VERSION 5.8 ;
BUSBITCHARS "[]" ;
DIVIDERCHAR "/" ;
UNITS
    DATABASE MICRONS 1000 ;
END UNITS

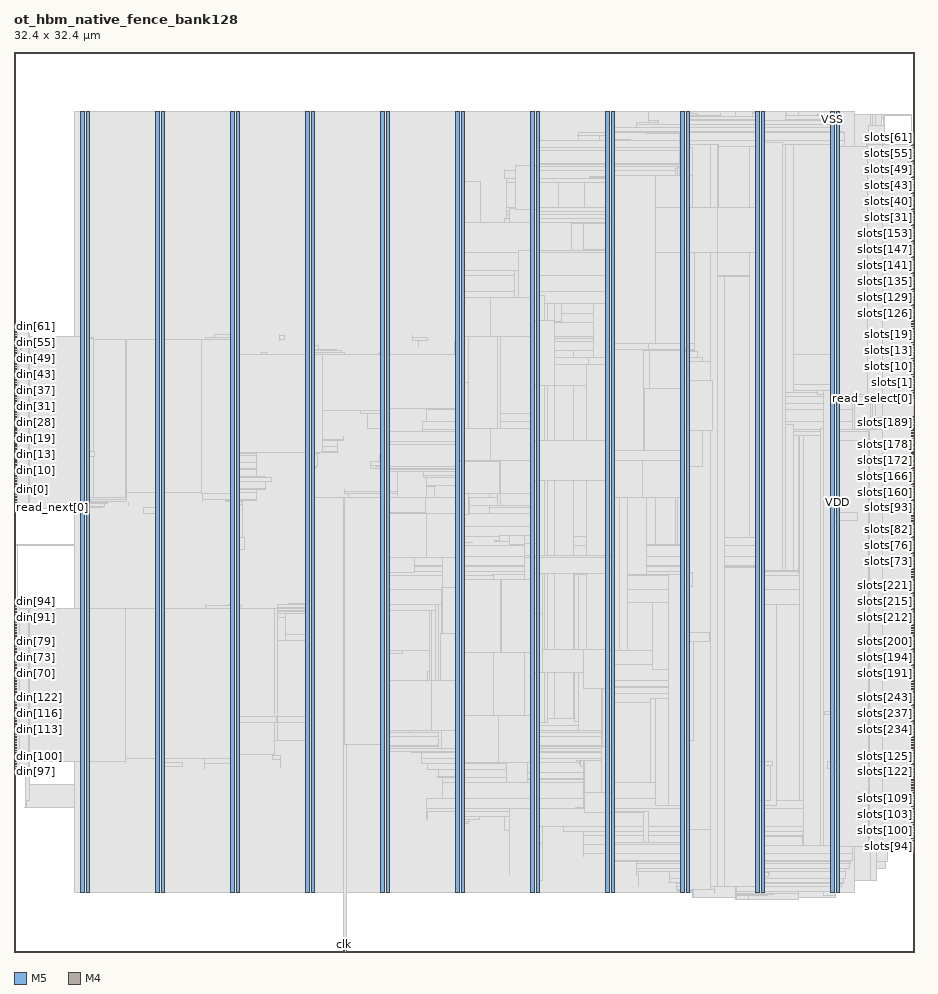
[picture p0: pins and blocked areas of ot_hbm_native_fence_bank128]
MACRO ot_hbm_native_fence_bank128
  FOREIGN ot_hbm_native_fence_bank128 0 0 ;
  CLASS BLOCK ;
  SIZE 32.4 BY 32.4 ;
  PIN clk
    DIRECTION INPUT ;
    USE SIGNAL ;
    PORT
      LAYER M5 ;
        RECT  11.856 0 11.88 0.084 ;
    END
  END clk
  PIN din[0]
    DIRECTION INPUT ;
    USE SIGNAL ;
    PORT
      LAYER M4 ;
        RECT  0 16.368 0.084 16.392 ;
    END
  END din[0]
  PIN din[100]
    DIRECTION INPUT ;
    USE SIGNAL ;
    PORT
      LAYER M4 ;
        RECT  0 6.768 0.084 6.792 ;
    END
  END din[100]
  PIN din[101]
    DIRECTION INPUT ;
    USE SIGNAL ;
    PORT
      LAYER M4 ;
        RECT  0 6.864 0.084 6.888 ;
    END
  END din[101]
  PIN din[102]
    DIRECTION INPUT ;
    USE SIGNAL ;
    PORT
      LAYER M4 ;
        RECT  0 6.96 0.084 6.984 ;
    END
  END din[102]
  PIN din[103]
    DIRECTION INPUT ;
    USE SIGNAL ;
    PORT
      LAYER M4 ;
        RECT  0 7.056 0.084 7.08 ;
    END
  END din[103]
  PIN din[104]
    DIRECTION INPUT ;
    USE SIGNAL ;
    PORT
      LAYER M4 ;
        RECT  0 7.152 0.084 7.176 ;
    END
  END din[104]
  PIN din[105]
    DIRECTION INPUT ;
    USE SIGNAL ;
    PORT
      LAYER M4 ;
        RECT  0 7.248 0.084 7.272 ;
    END
  END din[105]
  PIN din[106]
    DIRECTION INPUT ;
    USE SIGNAL ;
    PORT
      LAYER M4 ;
        RECT  0 7.344 0.084 7.368 ;
    END
  END din[106]
  PIN din[107]
    DIRECTION INPUT ;
    USE SIGNAL ;
    PORT
      LAYER M4 ;
        RECT  0 7.44 0.084 7.464 ;
    END
  END din[107]
  PIN din[108]
    DIRECTION INPUT ;
    USE SIGNAL ;
    PORT
      LAYER M4 ;
        RECT  0 7.536 0.084 7.56 ;
    END
  END din[108]
  PIN din[109]
    DIRECTION INPUT ;
    USE SIGNAL ;
    PORT
      LAYER M4 ;
        RECT  0 7.632 0.084 7.656 ;
    END
  END din[109]
  PIN din[10]
    DIRECTION INPUT ;
    USE SIGNAL ;
    PORT
      LAYER M4 ;
        RECT  0 17.328 0.084 17.352 ;
    END
  END din[10]
  PIN din[110]
    DIRECTION INPUT ;
    USE SIGNAL ;
    PORT
      LAYER M4 ;
        RECT  0 7.728 0.084 7.752 ;
    END
  END din[110]
  PIN din[111]
    DIRECTION INPUT ;
    USE SIGNAL ;
    PORT
      LAYER M4 ;
        RECT  0 7.824 0.084 7.848 ;
    END
  END din[111]
  PIN din[112]
    DIRECTION INPUT ;
    USE SIGNAL ;
    PORT
      LAYER M4 ;
        RECT  0 7.92 0.084 7.944 ;
    END
  END din[112]
  PIN din[113]
    DIRECTION INPUT ;
    USE SIGNAL ;
    PORT
      LAYER M4 ;
        RECT  0 8.016 0.084 8.04 ;
    END
  END din[113]
  PIN din[114]
    DIRECTION INPUT ;
    USE SIGNAL ;
    PORT
      LAYER M4 ;
        RECT  0 8.112 0.084 8.136 ;
    END
  END din[114]
  PIN din[115]
    DIRECTION INPUT ;
    USE SIGNAL ;
    PORT
      LAYER M4 ;
        RECT  0 8.208 0.084 8.232 ;
    END
  END din[115]
  PIN din[116]
    DIRECTION INPUT ;
    USE SIGNAL ;
    PORT
      LAYER M4 ;
        RECT  0 8.304 0.084 8.328 ;
    END
  END din[116]
  PIN din[117]
    DIRECTION INPUT ;
    USE SIGNAL ;
    PORT
      LAYER M4 ;
        RECT  0 8.4 0.084 8.424 ;
    END
  END din[117]
  PIN din[118]
    DIRECTION INPUT ;
    USE SIGNAL ;
    PORT
      LAYER M4 ;
        RECT  0 8.496 0.084 8.52 ;
    END
  END din[118]
  PIN din[119]
    DIRECTION INPUT ;
    USE SIGNAL ;
    PORT
      LAYER M4 ;
        RECT  0 8.592 0.084 8.616 ;
    END
  END din[119]
  PIN din[11]
    DIRECTION INPUT ;
    USE SIGNAL ;
    PORT
      LAYER M4 ;
        RECT  0 17.424 0.084 17.448 ;
    END
  END din[11]
  PIN din[120]
    DIRECTION INPUT ;
    USE SIGNAL ;
    PORT
      LAYER M4 ;
        RECT  0 8.688 0.084 8.712 ;
    END
  END din[120]
  PIN din[121]
    DIRECTION INPUT ;
    USE SIGNAL ;
    PORT
      LAYER M4 ;
        RECT  0 8.784 0.084 8.808 ;
    END
  END din[121]
  PIN din[122]
    DIRECTION INPUT ;
    USE SIGNAL ;
    PORT
      LAYER M4 ;
        RECT  0 8.88 0.084 8.904 ;
    END
  END din[122]
  PIN din[123]
    DIRECTION INPUT ;
    USE SIGNAL ;
    PORT
      LAYER M4 ;
        RECT  0 8.976 0.084 9 ;
    END
  END din[123]
  PIN din[124]
    DIRECTION INPUT ;
    USE SIGNAL ;
    PORT
      LAYER M4 ;
        RECT  0 9.072 0.084 9.096 ;
    END
  END din[124]
  PIN din[125]
    DIRECTION INPUT ;
    USE SIGNAL ;
    PORT
      LAYER M4 ;
        RECT  0 9.168 0.084 9.192 ;
    END
  END din[125]
  PIN din[126]
    DIRECTION INPUT ;
    USE SIGNAL ;
    PORT
      LAYER M4 ;
        RECT  0 9.264 0.084 9.288 ;
    END
  END din[126]
  PIN din[127]
    DIRECTION INPUT ;
    USE SIGNAL ;
    PORT
      LAYER M4 ;
        RECT  0 9.36 0.084 9.384 ;
    END
  END din[127]
  PIN din[12]
    DIRECTION INPUT ;
    USE SIGNAL ;
    PORT
      LAYER M4 ;
        RECT  0 17.52 0.084 17.544 ;
    END
  END din[12]
  PIN din[13]
    DIRECTION INPUT ;
    USE SIGNAL ;
    PORT
      LAYER M4 ;
        RECT  0 17.616 0.084 17.64 ;
    END
  END din[13]
  PIN din[14]
    DIRECTION INPUT ;
    USE SIGNAL ;
    PORT
      LAYER M4 ;
        RECT  0 17.712 0.084 17.736 ;
    END
  END din[14]
  PIN din[15]
    DIRECTION INPUT ;
    USE SIGNAL ;
    PORT
      LAYER M4 ;
        RECT  0 17.808 0.084 17.832 ;
    END
  END din[15]
  PIN din[16]
    DIRECTION INPUT ;
    USE SIGNAL ;
    PORT
      LAYER M4 ;
        RECT  0 17.904 0.084 17.928 ;
    END
  END din[16]
  PIN din[17]
    DIRECTION INPUT ;
    USE SIGNAL ;
    PORT
      LAYER M4 ;
        RECT  0 18 0.084 18.024 ;
    END
  END din[17]
  PIN din[18]
    DIRECTION INPUT ;
    USE SIGNAL ;
    PORT
      LAYER M4 ;
        RECT  0 18.096 0.084 18.12 ;
    END
  END din[18]
  PIN din[19]
    DIRECTION INPUT ;
    USE SIGNAL ;
    PORT
      LAYER M4 ;
        RECT  0 18.192 0.084 18.216 ;
    END
  END din[19]
  PIN din[1]
    DIRECTION INPUT ;
    USE SIGNAL ;
    PORT
      LAYER M4 ;
        RECT  0 16.464 0.084 16.488 ;
    END
  END din[1]
  PIN din[20]
    DIRECTION INPUT ;
    USE SIGNAL ;
    PORT
      LAYER M4 ;
        RECT  0 18.288 0.084 18.312 ;
    END
  END din[20]
  PIN din[21]
    DIRECTION INPUT ;
    USE SIGNAL ;
    PORT
      LAYER M4 ;
        RECT  0 18.384 0.084 18.408 ;
    END
  END din[21]
  PIN din[22]
    DIRECTION INPUT ;
    USE SIGNAL ;
    PORT
      LAYER M4 ;
        RECT  0 18.48 0.084 18.504 ;
    END
  END din[22]
  PIN din[23]
    DIRECTION INPUT ;
    USE SIGNAL ;
    PORT
      LAYER M4 ;
        RECT  0 18.576 0.084 18.6 ;
    END
  END din[23]
  PIN din[24]
    DIRECTION INPUT ;
    USE SIGNAL ;
    PORT
      LAYER M4 ;
        RECT  0 18.672 0.084 18.696 ;
    END
  END din[24]
  PIN din[25]
    DIRECTION INPUT ;
    USE SIGNAL ;
    PORT
      LAYER M4 ;
        RECT  0 18.768 0.084 18.792 ;
    END
  END din[25]
  PIN din[26]
    DIRECTION INPUT ;
    USE SIGNAL ;
    PORT
      LAYER M4 ;
        RECT  0 18.864 0.084 18.888 ;
    END
  END din[26]
  PIN din[27]
    DIRECTION INPUT ;
    USE SIGNAL ;
    PORT
      LAYER M4 ;
        RECT  0 18.96 0.084 18.984 ;
    END
  END din[27]
  PIN din[28]
    DIRECTION INPUT ;
    USE SIGNAL ;
    PORT
      LAYER M4 ;
        RECT  0 19.056 0.084 19.08 ;
    END
  END din[28]
  PIN din[29]
    DIRECTION INPUT ;
    USE SIGNAL ;
    PORT
      LAYER M4 ;
        RECT  0 19.152 0.084 19.176 ;
    END
  END din[29]
  PIN din[2]
    DIRECTION INPUT ;
    USE SIGNAL ;
    PORT
      LAYER M4 ;
        RECT  0 16.56 0.084 16.584 ;
    END
  END din[2]
  PIN din[30]
    DIRECTION INPUT ;
    USE SIGNAL ;
    PORT
      LAYER M4 ;
        RECT  0 19.248 0.084 19.272 ;
    END
  END din[30]
  PIN din[31]
    DIRECTION INPUT ;
    USE SIGNAL ;
    PORT
      LAYER M4 ;
        RECT  0 19.344 0.084 19.368 ;
    END
  END din[31]
  PIN din[32]
    DIRECTION INPUT ;
    USE SIGNAL ;
    PORT
      LAYER M4 ;
        RECT  0 19.44 0.084 19.464 ;
    END
  END din[32]
  PIN din[33]
    DIRECTION INPUT ;
    USE SIGNAL ;
    PORT
      LAYER M4 ;
        RECT  0 19.536 0.084 19.56 ;
    END
  END din[33]
  PIN din[34]
    DIRECTION INPUT ;
    USE SIGNAL ;
    PORT
      LAYER M4 ;
        RECT  0 19.632 0.084 19.656 ;
    END
  END din[34]
  PIN din[35]
    DIRECTION INPUT ;
    USE SIGNAL ;
    PORT
      LAYER M4 ;
        RECT  0 19.728 0.084 19.752 ;
    END
  END din[35]
  PIN din[36]
    DIRECTION INPUT ;
    USE SIGNAL ;
    PORT
      LAYER M4 ;
        RECT  0 19.824 0.084 19.848 ;
    END
  END din[36]
  PIN din[37]
    DIRECTION INPUT ;
    USE SIGNAL ;
    PORT
      LAYER M4 ;
        RECT  0 19.92 0.084 19.944 ;
    END
  END din[37]
  PIN din[38]
    DIRECTION INPUT ;
    USE SIGNAL ;
    PORT
      LAYER M4 ;
        RECT  0 20.016 0.084 20.04 ;
    END
  END din[38]
  PIN din[39]
    DIRECTION INPUT ;
    USE SIGNAL ;
    PORT
      LAYER M4 ;
        RECT  0 20.112 0.084 20.136 ;
    END
  END din[39]
  PIN din[3]
    DIRECTION INPUT ;
    USE SIGNAL ;
    PORT
      LAYER M4 ;
        RECT  0 16.656 0.084 16.68 ;
    END
  END din[3]
  PIN din[40]
    DIRECTION INPUT ;
    USE SIGNAL ;
    PORT
      LAYER M4 ;
        RECT  0 20.208 0.084 20.232 ;
    END
  END din[40]
  PIN din[41]
    DIRECTION INPUT ;
    USE SIGNAL ;
    PORT
      LAYER M4 ;
        RECT  0 20.304 0.084 20.328 ;
    END
  END din[41]
  PIN din[42]
    DIRECTION INPUT ;
    USE SIGNAL ;
    PORT
      LAYER M4 ;
        RECT  0 20.4 0.084 20.424 ;
    END
  END din[42]
  PIN din[43]
    DIRECTION INPUT ;
    USE SIGNAL ;
    PORT
      LAYER M4 ;
        RECT  0 20.496 0.084 20.52 ;
    END
  END din[43]
  PIN din[44]
    DIRECTION INPUT ;
    USE SIGNAL ;
    PORT
      LAYER M4 ;
        RECT  0 20.592 0.084 20.616 ;
    END
  END din[44]
  PIN din[45]
    DIRECTION INPUT ;
    USE SIGNAL ;
    PORT
      LAYER M4 ;
        RECT  0 20.688 0.084 20.712 ;
    END
  END din[45]
  PIN din[46]
    DIRECTION INPUT ;
    USE SIGNAL ;
    PORT
      LAYER M4 ;
        RECT  0 20.784 0.084 20.808 ;
    END
  END din[46]
  PIN din[47]
    DIRECTION INPUT ;
    USE SIGNAL ;
    PORT
      LAYER M4 ;
        RECT  0 20.88 0.084 20.904 ;
    END
  END din[47]
  PIN din[48]
    DIRECTION INPUT ;
    USE SIGNAL ;
    PORT
      LAYER M4 ;
        RECT  0 20.976 0.084 21 ;
    END
  END din[48]
  PIN din[49]
    DIRECTION INPUT ;
    USE SIGNAL ;
    PORT
      LAYER M4 ;
        RECT  0 21.072 0.084 21.096 ;
    END
  END din[49]
  PIN din[4]
    DIRECTION INPUT ;
    USE SIGNAL ;
    PORT
      LAYER M4 ;
        RECT  0 16.752 0.084 16.776 ;
    END
  END din[4]
  PIN din[50]
    DIRECTION INPUT ;
    USE SIGNAL ;
    PORT
      LAYER M4 ;
        RECT  0 21.168 0.084 21.192 ;
    END
  END din[50]
  PIN din[51]
    DIRECTION INPUT ;
    USE SIGNAL ;
    PORT
      LAYER M4 ;
        RECT  0 21.264 0.084 21.288 ;
    END
  END din[51]
  PIN din[52]
    DIRECTION INPUT ;
    USE SIGNAL ;
    PORT
      LAYER M4 ;
        RECT  0 21.36 0.084 21.384 ;
    END
  END din[52]
  PIN din[53]
    DIRECTION INPUT ;
    USE SIGNAL ;
    PORT
      LAYER M4 ;
        RECT  0 21.456 0.084 21.48 ;
    END
  END din[53]
  PIN din[54]
    DIRECTION INPUT ;
    USE SIGNAL ;
    PORT
      LAYER M4 ;
        RECT  0 21.552 0.084 21.576 ;
    END
  END din[54]
  PIN din[55]
    DIRECTION INPUT ;
    USE SIGNAL ;
    PORT
      LAYER M4 ;
        RECT  0 21.648 0.084 21.672 ;
    END
  END din[55]
  PIN din[56]
    DIRECTION INPUT ;
    USE SIGNAL ;
    PORT
      LAYER M4 ;
        RECT  0 21.744 0.084 21.768 ;
    END
  END din[56]
  PIN din[57]
    DIRECTION INPUT ;
    USE SIGNAL ;
    PORT
      LAYER M4 ;
        RECT  0 21.84 0.084 21.864 ;
    END
  END din[57]
  PIN din[58]
    DIRECTION INPUT ;
    USE SIGNAL ;
    PORT
      LAYER M4 ;
        RECT  0 21.936 0.084 21.96 ;
    END
  END din[58]
  PIN din[59]
    DIRECTION INPUT ;
    USE SIGNAL ;
    PORT
      LAYER M4 ;
        RECT  0 22.032 0.084 22.056 ;
    END
  END din[59]
  PIN din[5]
    DIRECTION INPUT ;
    USE SIGNAL ;
    PORT
      LAYER M4 ;
        RECT  0 16.848 0.084 16.872 ;
    END
  END din[5]
  PIN din[60]
    DIRECTION INPUT ;
    USE SIGNAL ;
    PORT
      LAYER M4 ;
        RECT  0 22.128 0.084 22.152 ;
    END
  END din[60]
  PIN din[61]
    DIRECTION INPUT ;
    USE SIGNAL ;
    PORT
      LAYER M4 ;
        RECT  0 22.224 0.084 22.248 ;
    END
  END din[61]
  PIN din[62]
    DIRECTION INPUT ;
    USE SIGNAL ;
    PORT
      LAYER M4 ;
        RECT  0 22.32 0.084 22.344 ;
    END
  END din[62]
  PIN din[63]
    DIRECTION INPUT ;
    USE SIGNAL ;
    PORT
      LAYER M4 ;
        RECT  0 22.416 0.084 22.44 ;
    END
  END din[63]
  PIN din[64]
    DIRECTION INPUT ;
    USE SIGNAL ;
    PORT
      LAYER M4 ;
        RECT  0 9.456 0.084 9.48 ;
    END
  END din[64]
  PIN din[65]
    DIRECTION INPUT ;
    USE SIGNAL ;
    PORT
      LAYER M4 ;
        RECT  0 9.552 0.084 9.576 ;
    END
  END din[65]
  PIN din[66]
    DIRECTION INPUT ;
    USE SIGNAL ;
    PORT
      LAYER M4 ;
        RECT  0 9.648 0.084 9.672 ;
    END
  END din[66]
  PIN din[67]
    DIRECTION INPUT ;
    USE SIGNAL ;
    PORT
      LAYER M4 ;
        RECT  0 9.744 0.084 9.768 ;
    END
  END din[67]
  PIN din[68]
    DIRECTION INPUT ;
    USE SIGNAL ;
    PORT
      LAYER M4 ;
        RECT  0 9.84 0.084 9.864 ;
    END
  END din[68]
  PIN din[69]
    DIRECTION INPUT ;
    USE SIGNAL ;
    PORT
      LAYER M4 ;
        RECT  0 9.936 0.084 9.96 ;
    END
  END din[69]
  PIN din[6]
    DIRECTION INPUT ;
    USE SIGNAL ;
    PORT
      LAYER M4 ;
        RECT  0 16.944 0.084 16.968 ;
    END
  END din[6]
  PIN din[70]
    DIRECTION INPUT ;
    USE SIGNAL ;
    PORT
      LAYER M4 ;
        RECT  0 10.032 0.084 10.056 ;
    END
  END din[70]
  PIN din[71]
    DIRECTION INPUT ;
    USE SIGNAL ;
    PORT
      LAYER M4 ;
        RECT  0 10.128 0.084 10.152 ;
    END
  END din[71]
  PIN din[72]
    DIRECTION INPUT ;
    USE SIGNAL ;
    PORT
      LAYER M4 ;
        RECT  0 10.224 0.084 10.248 ;
    END
  END din[72]
  PIN din[73]
    DIRECTION INPUT ;
    USE SIGNAL ;
    PORT
      LAYER M4 ;
        RECT  0 10.32 0.084 10.344 ;
    END
  END din[73]
  PIN din[74]
    DIRECTION INPUT ;
    USE SIGNAL ;
    PORT
      LAYER M4 ;
        RECT  0 10.416 0.084 10.44 ;
    END
  END din[74]
  PIN din[75]
    DIRECTION INPUT ;
    USE SIGNAL ;
    PORT
      LAYER M4 ;
        RECT  0 10.512 0.084 10.536 ;
    END
  END din[75]
  PIN din[76]
    DIRECTION INPUT ;
    USE SIGNAL ;
    PORT
      LAYER M4 ;
        RECT  0 10.608 0.084 10.632 ;
    END
  END din[76]
  PIN din[77]
    DIRECTION INPUT ;
    USE SIGNAL ;
    PORT
      LAYER M4 ;
        RECT  0 10.704 0.084 10.728 ;
    END
  END din[77]
  PIN din[78]
    DIRECTION INPUT ;
    USE SIGNAL ;
    PORT
      LAYER M4 ;
        RECT  0 10.8 0.084 10.824 ;
    END
  END din[78]
  PIN din[79]
    DIRECTION INPUT ;
    USE SIGNAL ;
    PORT
      LAYER M4 ;
        RECT  0 10.896 0.084 10.92 ;
    END
  END din[79]
  PIN din[7]
    DIRECTION INPUT ;
    USE SIGNAL ;
    PORT
      LAYER M4 ;
        RECT  0 17.04 0.084 17.064 ;
    END
  END din[7]
  PIN din[80]
    DIRECTION INPUT ;
    USE SIGNAL ;
    PORT
      LAYER M4 ;
        RECT  0 10.992 0.084 11.016 ;
    END
  END din[80]
  PIN din[81]
    DIRECTION INPUT ;
    USE SIGNAL ;
    PORT
      LAYER M4 ;
        RECT  0 11.088 0.084 11.112 ;
    END
  END din[81]
  PIN din[82]
    DIRECTION INPUT ;
    USE SIGNAL ;
    PORT
      LAYER M4 ;
        RECT  0 11.184 0.084 11.208 ;
    END
  END din[82]
  PIN din[83]
    DIRECTION INPUT ;
    USE SIGNAL ;
    PORT
      LAYER M4 ;
        RECT  0 11.28 0.084 11.304 ;
    END
  END din[83]
  PIN din[84]
    DIRECTION INPUT ;
    USE SIGNAL ;
    PORT
      LAYER M4 ;
        RECT  0 11.376 0.084 11.4 ;
    END
  END din[84]
  PIN din[85]
    DIRECTION INPUT ;
    USE SIGNAL ;
    PORT
      LAYER M4 ;
        RECT  0 11.472 0.084 11.496 ;
    END
  END din[85]
  PIN din[86]
    DIRECTION INPUT ;
    USE SIGNAL ;
    PORT
      LAYER M4 ;
        RECT  0 11.568 0.084 11.592 ;
    END
  END din[86]
  PIN din[87]
    DIRECTION INPUT ;
    USE SIGNAL ;
    PORT
      LAYER M4 ;
        RECT  0 11.664 0.084 11.688 ;
    END
  END din[87]
  PIN din[88]
    DIRECTION INPUT ;
    USE SIGNAL ;
    PORT
      LAYER M4 ;
        RECT  0 11.76 0.084 11.784 ;
    END
  END din[88]
  PIN din[89]
    DIRECTION INPUT ;
    USE SIGNAL ;
    PORT
      LAYER M4 ;
        RECT  0 11.856 0.084 11.88 ;
    END
  END din[89]
  PIN din[8]
    DIRECTION INPUT ;
    USE SIGNAL ;
    PORT
      LAYER M4 ;
        RECT  0 17.136 0.084 17.16 ;
    END
  END din[8]
  PIN din[90]
    DIRECTION INPUT ;
    USE SIGNAL ;
    PORT
      LAYER M4 ;
        RECT  0 11.952 0.084 11.976 ;
    END
  END din[90]
  PIN din[91]
    DIRECTION INPUT ;
    USE SIGNAL ;
    PORT
      LAYER M4 ;
        RECT  0 12.048 0.084 12.072 ;
    END
  END din[91]
  PIN din[92]
    DIRECTION INPUT ;
    USE SIGNAL ;
    PORT
      LAYER M4 ;
        RECT  0 12.144 0.084 12.168 ;
    END
  END din[92]
  PIN din[93]
    DIRECTION INPUT ;
    USE SIGNAL ;
    PORT
      LAYER M4 ;
        RECT  0 12.24 0.084 12.264 ;
    END
  END din[93]
  PIN din[94]
    DIRECTION INPUT ;
    USE SIGNAL ;
    PORT
      LAYER M4 ;
        RECT  0 12.336 0.084 12.36 ;
    END
  END din[94]
  PIN din[95]
    DIRECTION INPUT ;
    USE SIGNAL ;
    PORT
      LAYER M4 ;
        RECT  0 12.432 0.084 12.456 ;
    END
  END din[95]
  PIN din[96]
    DIRECTION INPUT ;
    USE SIGNAL ;
    PORT
      LAYER M4 ;
        RECT  0 6.384 0.084 6.408 ;
    END
  END din[96]
  PIN din[97]
    DIRECTION INPUT ;
    USE SIGNAL ;
    PORT
      LAYER M4 ;
        RECT  0 6.48 0.084 6.504 ;
    END
  END din[97]
  PIN din[98]
    DIRECTION INPUT ;
    USE SIGNAL ;
    PORT
      LAYER M4 ;
        RECT  0 6.576 0.084 6.6 ;
    END
  END din[98]
  PIN din[99]
    DIRECTION INPUT ;
    USE SIGNAL ;
    PORT
      LAYER M4 ;
        RECT  0 6.672 0.084 6.696 ;
    END
  END din[99]
  PIN din[9]
    DIRECTION INPUT ;
    USE SIGNAL ;
    PORT
      LAYER M4 ;
        RECT  0 17.232 0.084 17.256 ;
    END
  END din[9]
  PIN read_next[0]
    DIRECTION INPUT ;
    USE SIGNAL ;
    PORT
      LAYER M4 ;
        RECT  0 15.984 0.084 16.008 ;
    END
  END read_next[0]
  PIN read_next[1]
    DIRECTION INPUT ;
    USE SIGNAL ;
    PORT
      LAYER M4 ;
        RECT  0 16.08 0.084 16.104 ;
    END
  END read_next[1]
  PIN read_select[0]
    DIRECTION OUTPUT ;
    USE SIGNAL ;
    PORT
      LAYER M4 ;
        RECT  32.316 19.92 32.4 19.944 ;
    END
  END read_select[0]
  PIN read_select[1]
    DIRECTION OUTPUT ;
    USE SIGNAL ;
    PORT
      LAYER M4 ;
        RECT  32.316 20.016 32.4 20.04 ;
    END
  END read_select[1]
  PIN rst_n
    DIRECTION INPUT ;
    USE SIGNAL ;
    PORT
      LAYER M5 ;
        RECT  11.952 0 11.976 0.084 ;
    END
  END rst_n
  PIN slots[0]
    DIRECTION OUTPUT ;
    USE SIGNAL ;
    PORT
      LAYER M4 ;
        RECT  32.316 20.112 32.4 20.136 ;
    END
  END slots[0]
  PIN slots[100]
    DIRECTION OUTPUT ;
    USE SIGNAL ;
    PORT
      LAYER M4 ;
        RECT  32.316 4.368 32.4 4.392 ;
    END
  END slots[100]
  PIN slots[101]
    DIRECTION OUTPUT ;
    USE SIGNAL ;
    PORT
      LAYER M4 ;
        RECT  32.316 4.464 32.4 4.488 ;
    END
  END slots[101]
  PIN slots[102]
    DIRECTION OUTPUT ;
    USE SIGNAL ;
    PORT
      LAYER M4 ;
        RECT  32.316 4.56 32.4 4.584 ;
    END
  END slots[102]
  PIN slots[103]
    DIRECTION OUTPUT ;
    USE SIGNAL ;
    PORT
      LAYER M4 ;
        RECT  32.316 4.656 32.4 4.68 ;
    END
  END slots[103]
  PIN slots[104]
    DIRECTION OUTPUT ;
    USE SIGNAL ;
    PORT
      LAYER M4 ;
        RECT  32.316 4.752 32.4 4.776 ;
    END
  END slots[104]
  PIN slots[105]
    DIRECTION OUTPUT ;
    USE SIGNAL ;
    PORT
      LAYER M4 ;
        RECT  32.316 4.848 32.4 4.872 ;
    END
  END slots[105]
  PIN slots[106]
    DIRECTION OUTPUT ;
    USE SIGNAL ;
    PORT
      LAYER M4 ;
        RECT  32.316 4.944 32.4 4.968 ;
    END
  END slots[106]
  PIN slots[107]
    DIRECTION OUTPUT ;
    USE SIGNAL ;
    PORT
      LAYER M4 ;
        RECT  32.316 5.04 32.4 5.064 ;
    END
  END slots[107]
  PIN slots[108]
    DIRECTION OUTPUT ;
    USE SIGNAL ;
    PORT
      LAYER M4 ;
        RECT  32.316 5.136 32.4 5.16 ;
    END
  END slots[108]
  PIN slots[109]
    DIRECTION OUTPUT ;
    USE SIGNAL ;
    PORT
      LAYER M4 ;
        RECT  32.316 5.232 32.4 5.256 ;
    END
  END slots[109]
  PIN slots[10]
    DIRECTION OUTPUT ;
    USE SIGNAL ;
    PORT
      LAYER M4 ;
        RECT  32.316 21.072 32.4 21.096 ;
    END
  END slots[10]
  PIN slots[110]
    DIRECTION OUTPUT ;
    USE SIGNAL ;
    PORT
      LAYER M4 ;
        RECT  32.316 5.328 32.4 5.352 ;
    END
  END slots[110]
  PIN slots[111]
    DIRECTION OUTPUT ;
    USE SIGNAL ;
    PORT
      LAYER M4 ;
        RECT  32.316 5.424 32.4 5.448 ;
    END
  END slots[111]
  PIN slots[112]
    DIRECTION OUTPUT ;
    USE SIGNAL ;
    PORT
      LAYER M4 ;
        RECT  32.316 5.52 32.4 5.544 ;
    END
  END slots[112]
  PIN slots[113]
    DIRECTION OUTPUT ;
    USE SIGNAL ;
    PORT
      LAYER M4 ;
        RECT  32.316 5.616 32.4 5.64 ;
    END
  END slots[113]
  PIN slots[114]
    DIRECTION OUTPUT ;
    USE SIGNAL ;
    PORT
      LAYER M4 ;
        RECT  32.316 5.712 32.4 5.736 ;
    END
  END slots[114]
  PIN slots[115]
    DIRECTION OUTPUT ;
    USE SIGNAL ;
    PORT
      LAYER M4 ;
        RECT  32.316 5.808 32.4 5.832 ;
    END
  END slots[115]
  PIN slots[116]
    DIRECTION OUTPUT ;
    USE SIGNAL ;
    PORT
      LAYER M4 ;
        RECT  32.316 5.904 32.4 5.928 ;
    END
  END slots[116]
  PIN slots[117]
    DIRECTION OUTPUT ;
    USE SIGNAL ;
    PORT
      LAYER M4 ;
        RECT  32.316 6 32.4 6.024 ;
    END
  END slots[117]
  PIN slots[118]
    DIRECTION OUTPUT ;
    USE SIGNAL ;
    PORT
      LAYER M4 ;
        RECT  32.316 6.096 32.4 6.12 ;
    END
  END slots[118]
  PIN slots[119]
    DIRECTION OUTPUT ;
    USE SIGNAL ;
    PORT
      LAYER M4 ;
        RECT  32.316 6.192 32.4 6.216 ;
    END
  END slots[119]
  PIN slots[11]
    DIRECTION OUTPUT ;
    USE SIGNAL ;
    PORT
      LAYER M4 ;
        RECT  32.316 21.168 32.4 21.192 ;
    END
  END slots[11]
  PIN slots[120]
    DIRECTION OUTPUT ;
    USE SIGNAL ;
    PORT
      LAYER M4 ;
        RECT  32.316 6.288 32.4 6.312 ;
    END
  END slots[120]
  PIN slots[121]
    DIRECTION OUTPUT ;
    USE SIGNAL ;
    PORT
      LAYER M4 ;
        RECT  32.316 6.384 32.4 6.408 ;
    END
  END slots[121]
  PIN slots[122]
    DIRECTION OUTPUT ;
    USE SIGNAL ;
    PORT
      LAYER M4 ;
        RECT  32.316 6.48 32.4 6.504 ;
    END
  END slots[122]
  PIN slots[123]
    DIRECTION OUTPUT ;
    USE SIGNAL ;
    PORT
      LAYER M4 ;
        RECT  32.316 6.576 32.4 6.6 ;
    END
  END slots[123]
  PIN slots[124]
    DIRECTION OUTPUT ;
    USE SIGNAL ;
    PORT
      LAYER M4 ;
        RECT  32.316 6.672 32.4 6.696 ;
    END
  END slots[124]
  PIN slots[125]
    DIRECTION OUTPUT ;
    USE SIGNAL ;
    PORT
      LAYER M4 ;
        RECT  32.316 6.768 32.4 6.792 ;
    END
  END slots[125]
  PIN slots[126]
    DIRECTION OUTPUT ;
    USE SIGNAL ;
    PORT
      LAYER M4 ;
        RECT  32.316 22.992 32.4 23.016 ;
    END
  END slots[126]
  PIN slots[127]
    DIRECTION OUTPUT ;
    USE SIGNAL ;
    PORT
      LAYER M4 ;
        RECT  32.316 23.088 32.4 23.112 ;
    END
  END slots[127]
  PIN slots[128]
    DIRECTION OUTPUT ;
    USE SIGNAL ;
    PORT
      LAYER M4 ;
        RECT  32.316 23.184 32.4 23.208 ;
    END
  END slots[128]
  PIN slots[129]
    DIRECTION OUTPUT ;
    USE SIGNAL ;
    PORT
      LAYER M4 ;
        RECT  32.316 23.28 32.4 23.304 ;
    END
  END slots[129]
  PIN slots[12]
    DIRECTION OUTPUT ;
    USE SIGNAL ;
    PORT
      LAYER M4 ;
        RECT  32.316 21.264 32.4 21.288 ;
    END
  END slots[12]
  PIN slots[130]
    DIRECTION OUTPUT ;
    USE SIGNAL ;
    PORT
      LAYER M4 ;
        RECT  32.316 23.376 32.4 23.4 ;
    END
  END slots[130]
  PIN slots[131]
    DIRECTION OUTPUT ;
    USE SIGNAL ;
    PORT
      LAYER M4 ;
        RECT  32.316 23.472 32.4 23.496 ;
    END
  END slots[131]
  PIN slots[132]
    DIRECTION OUTPUT ;
    USE SIGNAL ;
    PORT
      LAYER M4 ;
        RECT  32.316 23.568 32.4 23.592 ;
    END
  END slots[132]
  PIN slots[133]
    DIRECTION OUTPUT ;
    USE SIGNAL ;
    PORT
      LAYER M4 ;
        RECT  32.316 23.664 32.4 23.688 ;
    END
  END slots[133]
  PIN slots[134]
    DIRECTION OUTPUT ;
    USE SIGNAL ;
    PORT
      LAYER M4 ;
        RECT  32.316 23.76 32.4 23.784 ;
    END
  END slots[134]
  PIN slots[135]
    DIRECTION OUTPUT ;
    USE SIGNAL ;
    PORT
      LAYER M4 ;
        RECT  32.316 23.856 32.4 23.88 ;
    END
  END slots[135]
  PIN slots[136]
    DIRECTION OUTPUT ;
    USE SIGNAL ;
    PORT
      LAYER M4 ;
        RECT  32.316 23.952 32.4 23.976 ;
    END
  END slots[136]
  PIN slots[137]
    DIRECTION OUTPUT ;
    USE SIGNAL ;
    PORT
      LAYER M4 ;
        RECT  32.316 24.048 32.4 24.072 ;
    END
  END slots[137]
  PIN slots[138]
    DIRECTION OUTPUT ;
    USE SIGNAL ;
    PORT
      LAYER M4 ;
        RECT  32.316 24.144 32.4 24.168 ;
    END
  END slots[138]
  PIN slots[139]
    DIRECTION OUTPUT ;
    USE SIGNAL ;
    PORT
      LAYER M4 ;
        RECT  32.316 24.24 32.4 24.264 ;
    END
  END slots[139]
  PIN slots[13]
    DIRECTION OUTPUT ;
    USE SIGNAL ;
    PORT
      LAYER M4 ;
        RECT  32.316 21.36 32.4 21.384 ;
    END
  END slots[13]
  PIN slots[140]
    DIRECTION OUTPUT ;
    USE SIGNAL ;
    PORT
      LAYER M4 ;
        RECT  32.316 24.336 32.4 24.36 ;
    END
  END slots[140]
  PIN slots[141]
    DIRECTION OUTPUT ;
    USE SIGNAL ;
    PORT
      LAYER M4 ;
        RECT  32.316 24.432 32.4 24.456 ;
    END
  END slots[141]
  PIN slots[142]
    DIRECTION OUTPUT ;
    USE SIGNAL ;
    PORT
      LAYER M4 ;
        RECT  32.316 24.528 32.4 24.552 ;
    END
  END slots[142]
  PIN slots[143]
    DIRECTION OUTPUT ;
    USE SIGNAL ;
    PORT
      LAYER M4 ;
        RECT  32.316 24.624 32.4 24.648 ;
    END
  END slots[143]
  PIN slots[144]
    DIRECTION OUTPUT ;
    USE SIGNAL ;
    PORT
      LAYER M4 ;
        RECT  32.316 24.72 32.4 24.744 ;
    END
  END slots[144]
  PIN slots[145]
    DIRECTION OUTPUT ;
    USE SIGNAL ;
    PORT
      LAYER M4 ;
        RECT  32.316 24.816 32.4 24.84 ;
    END
  END slots[145]
  PIN slots[146]
    DIRECTION OUTPUT ;
    USE SIGNAL ;
    PORT
      LAYER M4 ;
        RECT  32.316 24.912 32.4 24.936 ;
    END
  END slots[146]
  PIN slots[147]
    DIRECTION OUTPUT ;
    USE SIGNAL ;
    PORT
      LAYER M4 ;
        RECT  32.316 25.008 32.4 25.032 ;
    END
  END slots[147]
  PIN slots[148]
    DIRECTION OUTPUT ;
    USE SIGNAL ;
    PORT
      LAYER M4 ;
        RECT  32.316 25.104 32.4 25.128 ;
    END
  END slots[148]
  PIN slots[149]
    DIRECTION OUTPUT ;
    USE SIGNAL ;
    PORT
      LAYER M4 ;
        RECT  32.316 25.2 32.4 25.224 ;
    END
  END slots[149]
  PIN slots[14]
    DIRECTION OUTPUT ;
    USE SIGNAL ;
    PORT
      LAYER M4 ;
        RECT  32.316 21.456 32.4 21.48 ;
    END
  END slots[14]
  PIN slots[150]
    DIRECTION OUTPUT ;
    USE SIGNAL ;
    PORT
      LAYER M4 ;
        RECT  32.316 25.296 32.4 25.32 ;
    END
  END slots[150]
  PIN slots[151]
    DIRECTION OUTPUT ;
    USE SIGNAL ;
    PORT
      LAYER M4 ;
        RECT  32.316 25.392 32.4 25.416 ;
    END
  END slots[151]
  PIN slots[152]
    DIRECTION OUTPUT ;
    USE SIGNAL ;
    PORT
      LAYER M4 ;
        RECT  32.316 25.488 32.4 25.512 ;
    END
  END slots[152]
  PIN slots[153]
    DIRECTION OUTPUT ;
    USE SIGNAL ;
    PORT
      LAYER M4 ;
        RECT  32.316 25.584 32.4 25.608 ;
    END
  END slots[153]
  PIN slots[154]
    DIRECTION OUTPUT ;
    USE SIGNAL ;
    PORT
      LAYER M4 ;
        RECT  32.316 25.68 32.4 25.704 ;
    END
  END slots[154]
  PIN slots[155]
    DIRECTION OUTPUT ;
    USE SIGNAL ;
    PORT
      LAYER M4 ;
        RECT  32.316 25.776 32.4 25.8 ;
    END
  END slots[155]
  PIN slots[156]
    DIRECTION OUTPUT ;
    USE SIGNAL ;
    PORT
      LAYER M4 ;
        RECT  32.316 25.872 32.4 25.896 ;
    END
  END slots[156]
  PIN slots[157]
    DIRECTION OUTPUT ;
    USE SIGNAL ;
    PORT
      LAYER M4 ;
        RECT  32.316 25.968 32.4 25.992 ;
    END
  END slots[157]
  PIN slots[158]
    DIRECTION OUTPUT ;
    USE SIGNAL ;
    PORT
      LAYER M4 ;
        RECT  32.316 16.08 32.4 16.104 ;
    END
  END slots[158]
  PIN slots[159]
    DIRECTION OUTPUT ;
    USE SIGNAL ;
    PORT
      LAYER M4 ;
        RECT  32.316 16.176 32.4 16.2 ;
    END
  END slots[159]
  PIN slots[15]
    DIRECTION OUTPUT ;
    USE SIGNAL ;
    PORT
      LAYER M4 ;
        RECT  32.316 21.552 32.4 21.576 ;
    END
  END slots[15]
  PIN slots[160]
    DIRECTION OUTPUT ;
    USE SIGNAL ;
    PORT
      LAYER M4 ;
        RECT  32.316 16.272 32.4 16.296 ;
    END
  END slots[160]
  PIN slots[161]
    DIRECTION OUTPUT ;
    USE SIGNAL ;
    PORT
      LAYER M4 ;
        RECT  32.316 16.368 32.4 16.392 ;
    END
  END slots[161]
  PIN slots[162]
    DIRECTION OUTPUT ;
    USE SIGNAL ;
    PORT
      LAYER M4 ;
        RECT  32.316 16.464 32.4 16.488 ;
    END
  END slots[162]
  PIN slots[163]
    DIRECTION OUTPUT ;
    USE SIGNAL ;
    PORT
      LAYER M4 ;
        RECT  32.316 16.56 32.4 16.584 ;
    END
  END slots[163]
  PIN slots[164]
    DIRECTION OUTPUT ;
    USE SIGNAL ;
    PORT
      LAYER M4 ;
        RECT  32.316 16.656 32.4 16.68 ;
    END
  END slots[164]
  PIN slots[165]
    DIRECTION OUTPUT ;
    USE SIGNAL ;
    PORT
      LAYER M4 ;
        RECT  32.316 16.752 32.4 16.776 ;
    END
  END slots[165]
  PIN slots[166]
    DIRECTION OUTPUT ;
    USE SIGNAL ;
    PORT
      LAYER M4 ;
        RECT  32.316 16.848 32.4 16.872 ;
    END
  END slots[166]
  PIN slots[167]
    DIRECTION OUTPUT ;
    USE SIGNAL ;
    PORT
      LAYER M4 ;
        RECT  32.316 16.944 32.4 16.968 ;
    END
  END slots[167]
  PIN slots[168]
    DIRECTION OUTPUT ;
    USE SIGNAL ;
    PORT
      LAYER M4 ;
        RECT  32.316 17.04 32.4 17.064 ;
    END
  END slots[168]
  PIN slots[169]
    DIRECTION OUTPUT ;
    USE SIGNAL ;
    PORT
      LAYER M4 ;
        RECT  32.316 17.136 32.4 17.16 ;
    END
  END slots[169]
  PIN slots[16]
    DIRECTION OUTPUT ;
    USE SIGNAL ;
    PORT
      LAYER M4 ;
        RECT  32.316 21.648 32.4 21.672 ;
    END
  END slots[16]
  PIN slots[170]
    DIRECTION OUTPUT ;
    USE SIGNAL ;
    PORT
      LAYER M4 ;
        RECT  32.316 17.232 32.4 17.256 ;
    END
  END slots[170]
  PIN slots[171]
    DIRECTION OUTPUT ;
    USE SIGNAL ;
    PORT
      LAYER M4 ;
        RECT  32.316 17.328 32.4 17.352 ;
    END
  END slots[171]
  PIN slots[172]
    DIRECTION OUTPUT ;
    USE SIGNAL ;
    PORT
      LAYER M4 ;
        RECT  32.316 17.424 32.4 17.448 ;
    END
  END slots[172]
  PIN slots[173]
    DIRECTION OUTPUT ;
    USE SIGNAL ;
    PORT
      LAYER M4 ;
        RECT  32.316 17.52 32.4 17.544 ;
    END
  END slots[173]
  PIN slots[174]
    DIRECTION OUTPUT ;
    USE SIGNAL ;
    PORT
      LAYER M4 ;
        RECT  32.316 17.616 32.4 17.64 ;
    END
  END slots[174]
  PIN slots[175]
    DIRECTION OUTPUT ;
    USE SIGNAL ;
    PORT
      LAYER M4 ;
        RECT  32.316 17.712 32.4 17.736 ;
    END
  END slots[175]
  PIN slots[176]
    DIRECTION OUTPUT ;
    USE SIGNAL ;
    PORT
      LAYER M4 ;
        RECT  32.316 17.808 32.4 17.832 ;
    END
  END slots[176]
  PIN slots[177]
    DIRECTION OUTPUT ;
    USE SIGNAL ;
    PORT
      LAYER M4 ;
        RECT  32.316 17.904 32.4 17.928 ;
    END
  END slots[177]
  PIN slots[178]
    DIRECTION OUTPUT ;
    USE SIGNAL ;
    PORT
      LAYER M4 ;
        RECT  32.316 18 32.4 18.024 ;
    END
  END slots[178]
  PIN slots[179]
    DIRECTION OUTPUT ;
    USE SIGNAL ;
    PORT
      LAYER M4 ;
        RECT  32.316 18.096 32.4 18.12 ;
    END
  END slots[179]
  PIN slots[17]
    DIRECTION OUTPUT ;
    USE SIGNAL ;
    PORT
      LAYER M4 ;
        RECT  32.316 21.744 32.4 21.768 ;
    END
  END slots[17]
  PIN slots[180]
    DIRECTION OUTPUT ;
    USE SIGNAL ;
    PORT
      LAYER M4 ;
        RECT  32.316 18.192 32.4 18.216 ;
    END
  END slots[180]
  PIN slots[181]
    DIRECTION OUTPUT ;
    USE SIGNAL ;
    PORT
      LAYER M4 ;
        RECT  32.316 18.288 32.4 18.312 ;
    END
  END slots[181]
  PIN slots[182]
    DIRECTION OUTPUT ;
    USE SIGNAL ;
    PORT
      LAYER M4 ;
        RECT  32.316 18.384 32.4 18.408 ;
    END
  END slots[182]
  PIN slots[183]
    DIRECTION OUTPUT ;
    USE SIGNAL ;
    PORT
      LAYER M4 ;
        RECT  32.316 18.48 32.4 18.504 ;
    END
  END slots[183]
  PIN slots[184]
    DIRECTION OUTPUT ;
    USE SIGNAL ;
    PORT
      LAYER M4 ;
        RECT  32.316 18.576 32.4 18.6 ;
    END
  END slots[184]
  PIN slots[185]
    DIRECTION OUTPUT ;
    USE SIGNAL ;
    PORT
      LAYER M4 ;
        RECT  32.316 18.672 32.4 18.696 ;
    END
  END slots[185]
  PIN slots[186]
    DIRECTION OUTPUT ;
    USE SIGNAL ;
    PORT
      LAYER M4 ;
        RECT  32.316 18.768 32.4 18.792 ;
    END
  END slots[186]
  PIN slots[187]
    DIRECTION OUTPUT ;
    USE SIGNAL ;
    PORT
      LAYER M4 ;
        RECT  32.316 18.864 32.4 18.888 ;
    END
  END slots[187]
  PIN slots[188]
    DIRECTION OUTPUT ;
    USE SIGNAL ;
    PORT
      LAYER M4 ;
        RECT  32.316 18.96 32.4 18.984 ;
    END
  END slots[188]
  PIN slots[189]
    DIRECTION OUTPUT ;
    USE SIGNAL ;
    PORT
      LAYER M4 ;
        RECT  32.316 19.056 32.4 19.08 ;
    END
  END slots[189]
  PIN slots[18]
    DIRECTION OUTPUT ;
    USE SIGNAL ;
    PORT
      LAYER M4 ;
        RECT  32.316 21.84 32.4 21.864 ;
    END
  END slots[18]
  PIN slots[190]
    DIRECTION OUTPUT ;
    USE SIGNAL ;
    PORT
      LAYER M4 ;
        RECT  32.316 9.936 32.4 9.96 ;
    END
  END slots[190]
  PIN slots[191]
    DIRECTION OUTPUT ;
    USE SIGNAL ;
    PORT
      LAYER M4 ;
        RECT  32.316 10.032 32.4 10.056 ;
    END
  END slots[191]
  PIN slots[192]
    DIRECTION OUTPUT ;
    USE SIGNAL ;
    PORT
      LAYER M4 ;
        RECT  32.316 10.128 32.4 10.152 ;
    END
  END slots[192]
  PIN slots[193]
    DIRECTION OUTPUT ;
    USE SIGNAL ;
    PORT
      LAYER M4 ;
        RECT  32.316 10.224 32.4 10.248 ;
    END
  END slots[193]
  PIN slots[194]
    DIRECTION OUTPUT ;
    USE SIGNAL ;
    PORT
      LAYER M4 ;
        RECT  32.316 10.32 32.4 10.344 ;
    END
  END slots[194]
  PIN slots[195]
    DIRECTION OUTPUT ;
    USE SIGNAL ;
    PORT
      LAYER M4 ;
        RECT  32.316 10.416 32.4 10.44 ;
    END
  END slots[195]
  PIN slots[196]
    DIRECTION OUTPUT ;
    USE SIGNAL ;
    PORT
      LAYER M4 ;
        RECT  32.316 10.512 32.4 10.536 ;
    END
  END slots[196]
  PIN slots[197]
    DIRECTION OUTPUT ;
    USE SIGNAL ;
    PORT
      LAYER M4 ;
        RECT  32.316 10.608 32.4 10.632 ;
    END
  END slots[197]
  PIN slots[198]
    DIRECTION OUTPUT ;
    USE SIGNAL ;
    PORT
      LAYER M4 ;
        RECT  32.316 10.704 32.4 10.728 ;
    END
  END slots[198]
  PIN slots[199]
    DIRECTION OUTPUT ;
    USE SIGNAL ;
    PORT
      LAYER M4 ;
        RECT  32.316 10.8 32.4 10.824 ;
    END
  END slots[199]
  PIN slots[19]
    DIRECTION OUTPUT ;
    USE SIGNAL ;
    PORT
      LAYER M4 ;
        RECT  32.316 21.936 32.4 21.96 ;
    END
  END slots[19]
  PIN slots[1]
    DIRECTION OUTPUT ;
    USE SIGNAL ;
    PORT
      LAYER M4 ;
        RECT  32.316 20.208 32.4 20.232 ;
    END
  END slots[1]
  PIN slots[200]
    DIRECTION OUTPUT ;
    USE SIGNAL ;
    PORT
      LAYER M4 ;
        RECT  32.316 10.896 32.4 10.92 ;
    END
  END slots[200]
  PIN slots[201]
    DIRECTION OUTPUT ;
    USE SIGNAL ;
    PORT
      LAYER M4 ;
        RECT  32.316 10.992 32.4 11.016 ;
    END
  END slots[201]
  PIN slots[202]
    DIRECTION OUTPUT ;
    USE SIGNAL ;
    PORT
      LAYER M4 ;
        RECT  32.316 11.088 32.4 11.112 ;
    END
  END slots[202]
  PIN slots[203]
    DIRECTION OUTPUT ;
    USE SIGNAL ;
    PORT
      LAYER M4 ;
        RECT  32.316 11.184 32.4 11.208 ;
    END
  END slots[203]
  PIN slots[204]
    DIRECTION OUTPUT ;
    USE SIGNAL ;
    PORT
      LAYER M4 ;
        RECT  32.316 11.28 32.4 11.304 ;
    END
  END slots[204]
  PIN slots[205]
    DIRECTION OUTPUT ;
    USE SIGNAL ;
    PORT
      LAYER M4 ;
        RECT  32.316 11.376 32.4 11.4 ;
    END
  END slots[205]
  PIN slots[206]
    DIRECTION OUTPUT ;
    USE SIGNAL ;
    PORT
      LAYER M4 ;
        RECT  32.316 11.472 32.4 11.496 ;
    END
  END slots[206]
  PIN slots[207]
    DIRECTION OUTPUT ;
    USE SIGNAL ;
    PORT
      LAYER M4 ;
        RECT  32.316 11.568 32.4 11.592 ;
    END
  END slots[207]
  PIN slots[208]
    DIRECTION OUTPUT ;
    USE SIGNAL ;
    PORT
      LAYER M4 ;
        RECT  32.316 11.664 32.4 11.688 ;
    END
  END slots[208]
  PIN slots[209]
    DIRECTION OUTPUT ;
    USE SIGNAL ;
    PORT
      LAYER M4 ;
        RECT  32.316 11.76 32.4 11.784 ;
    END
  END slots[209]
  PIN slots[20]
    DIRECTION OUTPUT ;
    USE SIGNAL ;
    PORT
      LAYER M4 ;
        RECT  32.316 22.032 32.4 22.056 ;
    END
  END slots[20]
  PIN slots[210]
    DIRECTION OUTPUT ;
    USE SIGNAL ;
    PORT
      LAYER M4 ;
        RECT  32.316 11.856 32.4 11.88 ;
    END
  END slots[210]
  PIN slots[211]
    DIRECTION OUTPUT ;
    USE SIGNAL ;
    PORT
      LAYER M4 ;
        RECT  32.316 11.952 32.4 11.976 ;
    END
  END slots[211]
  PIN slots[212]
    DIRECTION OUTPUT ;
    USE SIGNAL ;
    PORT
      LAYER M4 ;
        RECT  32.316 12.048 32.4 12.072 ;
    END
  END slots[212]
  PIN slots[213]
    DIRECTION OUTPUT ;
    USE SIGNAL ;
    PORT
      LAYER M4 ;
        RECT  32.316 12.144 32.4 12.168 ;
    END
  END slots[213]
  PIN slots[214]
    DIRECTION OUTPUT ;
    USE SIGNAL ;
    PORT
      LAYER M4 ;
        RECT  32.316 12.24 32.4 12.264 ;
    END
  END slots[214]
  PIN slots[215]
    DIRECTION OUTPUT ;
    USE SIGNAL ;
    PORT
      LAYER M4 ;
        RECT  32.316 12.336 32.4 12.36 ;
    END
  END slots[215]
  PIN slots[216]
    DIRECTION OUTPUT ;
    USE SIGNAL ;
    PORT
      LAYER M4 ;
        RECT  32.316 12.432 32.4 12.456 ;
    END
  END slots[216]
  PIN slots[217]
    DIRECTION OUTPUT ;
    USE SIGNAL ;
    PORT
      LAYER M4 ;
        RECT  32.316 12.528 32.4 12.552 ;
    END
  END slots[217]
  PIN slots[218]
    DIRECTION OUTPUT ;
    USE SIGNAL ;
    PORT
      LAYER M4 ;
        RECT  32.316 12.624 32.4 12.648 ;
    END
  END slots[218]
  PIN slots[219]
    DIRECTION OUTPUT ;
    USE SIGNAL ;
    PORT
      LAYER M4 ;
        RECT  32.316 12.72 32.4 12.744 ;
    END
  END slots[219]
  PIN slots[21]
    DIRECTION OUTPUT ;
    USE SIGNAL ;
    PORT
      LAYER M4 ;
        RECT  32.316 22.128 32.4 22.152 ;
    END
  END slots[21]
  PIN slots[220]
    DIRECTION OUTPUT ;
    USE SIGNAL ;
    PORT
      LAYER M4 ;
        RECT  32.316 12.816 32.4 12.84 ;
    END
  END slots[220]
  PIN slots[221]
    DIRECTION OUTPUT ;
    USE SIGNAL ;
    PORT
      LAYER M4 ;
        RECT  32.316 12.912 32.4 12.936 ;
    END
  END slots[221]
  PIN slots[222]
    DIRECTION OUTPUT ;
    USE SIGNAL ;
    PORT
      LAYER M4 ;
        RECT  32.316 6.864 32.4 6.888 ;
    END
  END slots[222]
  PIN slots[223]
    DIRECTION OUTPUT ;
    USE SIGNAL ;
    PORT
      LAYER M4 ;
        RECT  32.316 6.96 32.4 6.984 ;
    END
  END slots[223]
  PIN slots[224]
    DIRECTION OUTPUT ;
    USE SIGNAL ;
    PORT
      LAYER M4 ;
        RECT  32.316 7.056 32.4 7.08 ;
    END
  END slots[224]
  PIN slots[225]
    DIRECTION OUTPUT ;
    USE SIGNAL ;
    PORT
      LAYER M4 ;
        RECT  32.316 7.152 32.4 7.176 ;
    END
  END slots[225]
  PIN slots[226]
    DIRECTION OUTPUT ;
    USE SIGNAL ;
    PORT
      LAYER M4 ;
        RECT  32.316 7.248 32.4 7.272 ;
    END
  END slots[226]
  PIN slots[227]
    DIRECTION OUTPUT ;
    USE SIGNAL ;
    PORT
      LAYER M4 ;
        RECT  32.316 7.344 32.4 7.368 ;
    END
  END slots[227]
  PIN slots[228]
    DIRECTION OUTPUT ;
    USE SIGNAL ;
    PORT
      LAYER M4 ;
        RECT  32.316 7.44 32.4 7.464 ;
    END
  END slots[228]
  PIN slots[229]
    DIRECTION OUTPUT ;
    USE SIGNAL ;
    PORT
      LAYER M4 ;
        RECT  32.316 7.536 32.4 7.56 ;
    END
  END slots[229]
  PIN slots[22]
    DIRECTION OUTPUT ;
    USE SIGNAL ;
    PORT
      LAYER M4 ;
        RECT  32.316 22.224 32.4 22.248 ;
    END
  END slots[22]
  PIN slots[230]
    DIRECTION OUTPUT ;
    USE SIGNAL ;
    PORT
      LAYER M4 ;
        RECT  32.316 7.632 32.4 7.656 ;
    END
  END slots[230]
  PIN slots[231]
    DIRECTION OUTPUT ;
    USE SIGNAL ;
    PORT
      LAYER M4 ;
        RECT  32.316 7.728 32.4 7.752 ;
    END
  END slots[231]
  PIN slots[232]
    DIRECTION OUTPUT ;
    USE SIGNAL ;
    PORT
      LAYER M4 ;
        RECT  32.316 7.824 32.4 7.848 ;
    END
  END slots[232]
  PIN slots[233]
    DIRECTION OUTPUT ;
    USE SIGNAL ;
    PORT
      LAYER M4 ;
        RECT  32.316 7.92 32.4 7.944 ;
    END
  END slots[233]
  PIN slots[234]
    DIRECTION OUTPUT ;
    USE SIGNAL ;
    PORT
      LAYER M4 ;
        RECT  32.316 8.016 32.4 8.04 ;
    END
  END slots[234]
  PIN slots[235]
    DIRECTION OUTPUT ;
    USE SIGNAL ;
    PORT
      LAYER M4 ;
        RECT  32.316 8.112 32.4 8.136 ;
    END
  END slots[235]
  PIN slots[236]
    DIRECTION OUTPUT ;
    USE SIGNAL ;
    PORT
      LAYER M4 ;
        RECT  32.316 8.208 32.4 8.232 ;
    END
  END slots[236]
  PIN slots[237]
    DIRECTION OUTPUT ;
    USE SIGNAL ;
    PORT
      LAYER M4 ;
        RECT  32.316 8.304 32.4 8.328 ;
    END
  END slots[237]
  PIN slots[238]
    DIRECTION OUTPUT ;
    USE SIGNAL ;
    PORT
      LAYER M4 ;
        RECT  32.316 8.4 32.4 8.424 ;
    END
  END slots[238]
  PIN slots[239]
    DIRECTION OUTPUT ;
    USE SIGNAL ;
    PORT
      LAYER M4 ;
        RECT  32.316 8.496 32.4 8.52 ;
    END
  END slots[239]
  PIN slots[23]
    DIRECTION OUTPUT ;
    USE SIGNAL ;
    PORT
      LAYER M4 ;
        RECT  32.316 22.32 32.4 22.344 ;
    END
  END slots[23]
  PIN slots[240]
    DIRECTION OUTPUT ;
    USE SIGNAL ;
    PORT
      LAYER M4 ;
        RECT  32.316 8.592 32.4 8.616 ;
    END
  END slots[240]
  PIN slots[241]
    DIRECTION OUTPUT ;
    USE SIGNAL ;
    PORT
      LAYER M4 ;
        RECT  32.316 8.688 32.4 8.712 ;
    END
  END slots[241]
  PIN slots[242]
    DIRECTION OUTPUT ;
    USE SIGNAL ;
    PORT
      LAYER M4 ;
        RECT  32.316 8.784 32.4 8.808 ;
    END
  END slots[242]
  PIN slots[243]
    DIRECTION OUTPUT ;
    USE SIGNAL ;
    PORT
      LAYER M4 ;
        RECT  32.316 8.88 32.4 8.904 ;
    END
  END slots[243]
  PIN slots[244]
    DIRECTION OUTPUT ;
    USE SIGNAL ;
    PORT
      LAYER M4 ;
        RECT  32.316 8.976 32.4 9 ;
    END
  END slots[244]
  PIN slots[245]
    DIRECTION OUTPUT ;
    USE SIGNAL ;
    PORT
      LAYER M4 ;
        RECT  32.316 9.072 32.4 9.096 ;
    END
  END slots[245]
  PIN slots[246]
    DIRECTION OUTPUT ;
    USE SIGNAL ;
    PORT
      LAYER M4 ;
        RECT  32.316 9.168 32.4 9.192 ;
    END
  END slots[246]
  PIN slots[247]
    DIRECTION OUTPUT ;
    USE SIGNAL ;
    PORT
      LAYER M4 ;
        RECT  32.316 9.264 32.4 9.288 ;
    END
  END slots[247]
  PIN slots[248]
    DIRECTION OUTPUT ;
    USE SIGNAL ;
    PORT
      LAYER M4 ;
        RECT  32.316 9.36 32.4 9.384 ;
    END
  END slots[248]
  PIN slots[249]
    DIRECTION OUTPUT ;
    USE SIGNAL ;
    PORT
      LAYER M4 ;
        RECT  32.316 9.456 32.4 9.48 ;
    END
  END slots[249]
  PIN slots[24]
    DIRECTION OUTPUT ;
    USE SIGNAL ;
    PORT
      LAYER M4 ;
        RECT  32.316 22.416 32.4 22.44 ;
    END
  END slots[24]
  PIN slots[250]
    DIRECTION OUTPUT ;
    USE SIGNAL ;
    PORT
      LAYER M4 ;
        RECT  32.316 9.552 32.4 9.576 ;
    END
  END slots[250]
  PIN slots[251]
    DIRECTION OUTPUT ;
    USE SIGNAL ;
    PORT
      LAYER M4 ;
        RECT  32.316 9.648 32.4 9.672 ;
    END
  END slots[251]
  PIN slots[252]
    DIRECTION OUTPUT ;
    USE SIGNAL ;
    PORT
      LAYER M4 ;
        RECT  32.316 9.744 32.4 9.768 ;
    END
  END slots[252]
  PIN slots[253]
    DIRECTION OUTPUT ;
    USE SIGNAL ;
    PORT
      LAYER M4 ;
        RECT  32.316 9.84 32.4 9.864 ;
    END
  END slots[253]
  PIN slots[254]
    DIRECTION OUTPUT ;
    USE SIGNAL ;
    PORT
      LAYER M4 ;
        RECT  32.316 19.152 32.4 19.176 ;
    END
  END slots[254]
  PIN slots[255]
    DIRECTION OUTPUT ;
    USE SIGNAL ;
    PORT
      LAYER M4 ;
        RECT  32.316 19.248 32.4 19.272 ;
    END
  END slots[255]
  PIN slots[25]
    DIRECTION OUTPUT ;
    USE SIGNAL ;
    PORT
      LAYER M4 ;
        RECT  32.316 22.512 32.4 22.536 ;
    END
  END slots[25]
  PIN slots[26]
    DIRECTION OUTPUT ;
    USE SIGNAL ;
    PORT
      LAYER M4 ;
        RECT  32.316 22.608 32.4 22.632 ;
    END
  END slots[26]
  PIN slots[27]
    DIRECTION OUTPUT ;
    USE SIGNAL ;
    PORT
      LAYER M4 ;
        RECT  32.316 22.704 32.4 22.728 ;
    END
  END slots[27]
  PIN slots[28]
    DIRECTION OUTPUT ;
    USE SIGNAL ;
    PORT
      LAYER M4 ;
        RECT  32.316 22.8 32.4 22.824 ;
    END
  END slots[28]
  PIN slots[29]
    DIRECTION OUTPUT ;
    USE SIGNAL ;
    PORT
      LAYER M4 ;
        RECT  32.316 22.896 32.4 22.92 ;
    END
  END slots[29]
  PIN slots[2]
    DIRECTION OUTPUT ;
    USE SIGNAL ;
    PORT
      LAYER M4 ;
        RECT  32.316 20.304 32.4 20.328 ;
    END
  END slots[2]
  PIN slots[30]
    DIRECTION OUTPUT ;
    USE SIGNAL ;
    PORT
      LAYER M4 ;
        RECT  32.316 26.064 32.4 26.088 ;
    END
  END slots[30]
  PIN slots[31]
    DIRECTION OUTPUT ;
    USE SIGNAL ;
    PORT
      LAYER M4 ;
        RECT  32.316 26.16 32.4 26.184 ;
    END
  END slots[31]
  PIN slots[32]
    DIRECTION OUTPUT ;
    USE SIGNAL ;
    PORT
      LAYER M4 ;
        RECT  32.316 26.256 32.4 26.28 ;
    END
  END slots[32]
  PIN slots[33]
    DIRECTION OUTPUT ;
    USE SIGNAL ;
    PORT
      LAYER M4 ;
        RECT  32.316 26.352 32.4 26.376 ;
    END
  END slots[33]
  PIN slots[34]
    DIRECTION OUTPUT ;
    USE SIGNAL ;
    PORT
      LAYER M4 ;
        RECT  32.316 26.448 32.4 26.472 ;
    END
  END slots[34]
  PIN slots[35]
    DIRECTION OUTPUT ;
    USE SIGNAL ;
    PORT
      LAYER M4 ;
        RECT  32.316 26.544 32.4 26.568 ;
    END
  END slots[35]
  PIN slots[36]
    DIRECTION OUTPUT ;
    USE SIGNAL ;
    PORT
      LAYER M4 ;
        RECT  32.316 26.64 32.4 26.664 ;
    END
  END slots[36]
  PIN slots[37]
    DIRECTION OUTPUT ;
    USE SIGNAL ;
    PORT
      LAYER M4 ;
        RECT  32.316 26.736 32.4 26.76 ;
    END
  END slots[37]
  PIN slots[38]
    DIRECTION OUTPUT ;
    USE SIGNAL ;
    PORT
      LAYER M4 ;
        RECT  32.316 26.832 32.4 26.856 ;
    END
  END slots[38]
  PIN slots[39]
    DIRECTION OUTPUT ;
    USE SIGNAL ;
    PORT
      LAYER M4 ;
        RECT  32.316 26.928 32.4 26.952 ;
    END
  END slots[39]
  PIN slots[3]
    DIRECTION OUTPUT ;
    USE SIGNAL ;
    PORT
      LAYER M4 ;
        RECT  32.316 20.4 32.4 20.424 ;
    END
  END slots[3]
  PIN slots[40]
    DIRECTION OUTPUT ;
    USE SIGNAL ;
    PORT
      LAYER M4 ;
        RECT  32.316 27.024 32.4 27.048 ;
    END
  END slots[40]
  PIN slots[41]
    DIRECTION OUTPUT ;
    USE SIGNAL ;
    PORT
      LAYER M4 ;
        RECT  32.316 27.12 32.4 27.144 ;
    END
  END slots[41]
  PIN slots[42]
    DIRECTION OUTPUT ;
    USE SIGNAL ;
    PORT
      LAYER M4 ;
        RECT  32.316 27.216 32.4 27.24 ;
    END
  END slots[42]
  PIN slots[43]
    DIRECTION OUTPUT ;
    USE SIGNAL ;
    PORT
      LAYER M4 ;
        RECT  32.316 27.312 32.4 27.336 ;
    END
  END slots[43]
  PIN slots[44]
    DIRECTION OUTPUT ;
    USE SIGNAL ;
    PORT
      LAYER M4 ;
        RECT  32.316 27.408 32.4 27.432 ;
    END
  END slots[44]
  PIN slots[45]
    DIRECTION OUTPUT ;
    USE SIGNAL ;
    PORT
      LAYER M4 ;
        RECT  32.316 27.504 32.4 27.528 ;
    END
  END slots[45]
  PIN slots[46]
    DIRECTION OUTPUT ;
    USE SIGNAL ;
    PORT
      LAYER M4 ;
        RECT  32.316 27.6 32.4 27.624 ;
    END
  END slots[46]
  PIN slots[47]
    DIRECTION OUTPUT ;
    USE SIGNAL ;
    PORT
      LAYER M4 ;
        RECT  32.316 27.696 32.4 27.72 ;
    END
  END slots[47]
  PIN slots[48]
    DIRECTION OUTPUT ;
    USE SIGNAL ;
    PORT
      LAYER M4 ;
        RECT  32.316 27.792 32.4 27.816 ;
    END
  END slots[48]
  PIN slots[49]
    DIRECTION OUTPUT ;
    USE SIGNAL ;
    PORT
      LAYER M4 ;
        RECT  32.316 27.888 32.4 27.912 ;
    END
  END slots[49]
  PIN slots[4]
    DIRECTION OUTPUT ;
    USE SIGNAL ;
    PORT
      LAYER M4 ;
        RECT  32.316 20.496 32.4 20.52 ;
    END
  END slots[4]
  PIN slots[50]
    DIRECTION OUTPUT ;
    USE SIGNAL ;
    PORT
      LAYER M4 ;
        RECT  32.316 27.984 32.4 28.008 ;
    END
  END slots[50]
  PIN slots[51]
    DIRECTION OUTPUT ;
    USE SIGNAL ;
    PORT
      LAYER M4 ;
        RECT  32.316 28.08 32.4 28.104 ;
    END
  END slots[51]
  PIN slots[52]
    DIRECTION OUTPUT ;
    USE SIGNAL ;
    PORT
      LAYER M4 ;
        RECT  32.316 28.176 32.4 28.2 ;
    END
  END slots[52]
  PIN slots[53]
    DIRECTION OUTPUT ;
    USE SIGNAL ;
    PORT
      LAYER M4 ;
        RECT  32.316 28.272 32.4 28.296 ;
    END
  END slots[53]
  PIN slots[54]
    DIRECTION OUTPUT ;
    USE SIGNAL ;
    PORT
      LAYER M4 ;
        RECT  32.316 28.368 32.4 28.392 ;
    END
  END slots[54]
  PIN slots[55]
    DIRECTION OUTPUT ;
    USE SIGNAL ;
    PORT
      LAYER M4 ;
        RECT  32.316 28.464 32.4 28.488 ;
    END
  END slots[55]
  PIN slots[56]
    DIRECTION OUTPUT ;
    USE SIGNAL ;
    PORT
      LAYER M4 ;
        RECT  32.316 28.56 32.4 28.584 ;
    END
  END slots[56]
  PIN slots[57]
    DIRECTION OUTPUT ;
    USE SIGNAL ;
    PORT
      LAYER M4 ;
        RECT  32.316 28.656 32.4 28.68 ;
    END
  END slots[57]
  PIN slots[58]
    DIRECTION OUTPUT ;
    USE SIGNAL ;
    PORT
      LAYER M4 ;
        RECT  32.316 28.752 32.4 28.776 ;
    END
  END slots[58]
  PIN slots[59]
    DIRECTION OUTPUT ;
    USE SIGNAL ;
    PORT
      LAYER M4 ;
        RECT  32.316 28.848 32.4 28.872 ;
    END
  END slots[59]
  PIN slots[5]
    DIRECTION OUTPUT ;
    USE SIGNAL ;
    PORT
      LAYER M4 ;
        RECT  32.316 20.592 32.4 20.616 ;
    END
  END slots[5]
  PIN slots[60]
    DIRECTION OUTPUT ;
    USE SIGNAL ;
    PORT
      LAYER M4 ;
        RECT  32.316 28.944 32.4 28.968 ;
    END
  END slots[60]
  PIN slots[61]
    DIRECTION OUTPUT ;
    USE SIGNAL ;
    PORT
      LAYER M4 ;
        RECT  32.316 29.04 32.4 29.064 ;
    END
  END slots[61]
  PIN slots[62]
    DIRECTION OUTPUT ;
    USE SIGNAL ;
    PORT
      LAYER M4 ;
        RECT  32.316 13.008 32.4 13.032 ;
    END
  END slots[62]
  PIN slots[63]
    DIRECTION OUTPUT ;
    USE SIGNAL ;
    PORT
      LAYER M4 ;
        RECT  32.316 13.104 32.4 13.128 ;
    END
  END slots[63]
  PIN slots[64]
    DIRECTION OUTPUT ;
    USE SIGNAL ;
    PORT
      LAYER M4 ;
        RECT  32.316 13.2 32.4 13.224 ;
    END
  END slots[64]
  PIN slots[65]
    DIRECTION OUTPUT ;
    USE SIGNAL ;
    PORT
      LAYER M4 ;
        RECT  32.316 13.296 32.4 13.32 ;
    END
  END slots[65]
  PIN slots[66]
    DIRECTION OUTPUT ;
    USE SIGNAL ;
    PORT
      LAYER M4 ;
        RECT  32.316 13.392 32.4 13.416 ;
    END
  END slots[66]
  PIN slots[67]
    DIRECTION OUTPUT ;
    USE SIGNAL ;
    PORT
      LAYER M4 ;
        RECT  32.316 13.488 32.4 13.512 ;
    END
  END slots[67]
  PIN slots[68]
    DIRECTION OUTPUT ;
    USE SIGNAL ;
    PORT
      LAYER M4 ;
        RECT  32.316 13.584 32.4 13.608 ;
    END
  END slots[68]
  PIN slots[69]
    DIRECTION OUTPUT ;
    USE SIGNAL ;
    PORT
      LAYER M4 ;
        RECT  32.316 13.68 32.4 13.704 ;
    END
  END slots[69]
  PIN slots[6]
    DIRECTION OUTPUT ;
    USE SIGNAL ;
    PORT
      LAYER M4 ;
        RECT  32.316 20.688 32.4 20.712 ;
    END
  END slots[6]
  PIN slots[70]
    DIRECTION OUTPUT ;
    USE SIGNAL ;
    PORT
      LAYER M4 ;
        RECT  32.316 13.776 32.4 13.8 ;
    END
  END slots[70]
  PIN slots[71]
    DIRECTION OUTPUT ;
    USE SIGNAL ;
    PORT
      LAYER M4 ;
        RECT  32.316 13.872 32.4 13.896 ;
    END
  END slots[71]
  PIN slots[72]
    DIRECTION OUTPUT ;
    USE SIGNAL ;
    PORT
      LAYER M4 ;
        RECT  32.316 13.968 32.4 13.992 ;
    END
  END slots[72]
  PIN slots[73]
    DIRECTION OUTPUT ;
    USE SIGNAL ;
    PORT
      LAYER M4 ;
        RECT  32.316 14.064 32.4 14.088 ;
    END
  END slots[73]
  PIN slots[74]
    DIRECTION OUTPUT ;
    USE SIGNAL ;
    PORT
      LAYER M4 ;
        RECT  32.316 14.16 32.4 14.184 ;
    END
  END slots[74]
  PIN slots[75]
    DIRECTION OUTPUT ;
    USE SIGNAL ;
    PORT
      LAYER M4 ;
        RECT  32.316 14.256 32.4 14.28 ;
    END
  END slots[75]
  PIN slots[76]
    DIRECTION OUTPUT ;
    USE SIGNAL ;
    PORT
      LAYER M4 ;
        RECT  32.316 14.352 32.4 14.376 ;
    END
  END slots[76]
  PIN slots[77]
    DIRECTION OUTPUT ;
    USE SIGNAL ;
    PORT
      LAYER M4 ;
        RECT  32.316 14.448 32.4 14.472 ;
    END
  END slots[77]
  PIN slots[78]
    DIRECTION OUTPUT ;
    USE SIGNAL ;
    PORT
      LAYER M4 ;
        RECT  32.316 14.544 32.4 14.568 ;
    END
  END slots[78]
  PIN slots[79]
    DIRECTION OUTPUT ;
    USE SIGNAL ;
    PORT
      LAYER M4 ;
        RECT  32.316 14.64 32.4 14.664 ;
    END
  END slots[79]
  PIN slots[7]
    DIRECTION OUTPUT ;
    USE SIGNAL ;
    PORT
      LAYER M4 ;
        RECT  32.316 20.784 32.4 20.808 ;
    END
  END slots[7]
  PIN slots[80]
    DIRECTION OUTPUT ;
    USE SIGNAL ;
    PORT
      LAYER M4 ;
        RECT  32.316 14.736 32.4 14.76 ;
    END
  END slots[80]
  PIN slots[81]
    DIRECTION OUTPUT ;
    USE SIGNAL ;
    PORT
      LAYER M4 ;
        RECT  32.316 14.832 32.4 14.856 ;
    END
  END slots[81]
  PIN slots[82]
    DIRECTION OUTPUT ;
    USE SIGNAL ;
    PORT
      LAYER M4 ;
        RECT  32.316 14.928 32.4 14.952 ;
    END
  END slots[82]
  PIN slots[83]
    DIRECTION OUTPUT ;
    USE SIGNAL ;
    PORT
      LAYER M4 ;
        RECT  32.316 15.024 32.4 15.048 ;
    END
  END slots[83]
  PIN slots[84]
    DIRECTION OUTPUT ;
    USE SIGNAL ;
    PORT
      LAYER M4 ;
        RECT  32.316 15.12 32.4 15.144 ;
    END
  END slots[84]
  PIN slots[85]
    DIRECTION OUTPUT ;
    USE SIGNAL ;
    PORT
      LAYER M4 ;
        RECT  32.316 15.216 32.4 15.24 ;
    END
  END slots[85]
  PIN slots[86]
    DIRECTION OUTPUT ;
    USE SIGNAL ;
    PORT
      LAYER M4 ;
        RECT  32.316 15.312 32.4 15.336 ;
    END
  END slots[86]
  PIN slots[87]
    DIRECTION OUTPUT ;
    USE SIGNAL ;
    PORT
      LAYER M4 ;
        RECT  32.316 15.408 32.4 15.432 ;
    END
  END slots[87]
  PIN slots[88]
    DIRECTION OUTPUT ;
    USE SIGNAL ;
    PORT
      LAYER M4 ;
        RECT  32.316 15.504 32.4 15.528 ;
    END
  END slots[88]
  PIN slots[89]
    DIRECTION OUTPUT ;
    USE SIGNAL ;
    PORT
      LAYER M4 ;
        RECT  32.316 15.6 32.4 15.624 ;
    END
  END slots[89]
  PIN slots[8]
    DIRECTION OUTPUT ;
    USE SIGNAL ;
    PORT
      LAYER M4 ;
        RECT  32.316 20.88 32.4 20.904 ;
    END
  END slots[8]
  PIN slots[90]
    DIRECTION OUTPUT ;
    USE SIGNAL ;
    PORT
      LAYER M4 ;
        RECT  32.316 15.696 32.4 15.72 ;
    END
  END slots[90]
  PIN slots[91]
    DIRECTION OUTPUT ;
    USE SIGNAL ;
    PORT
      LAYER M4 ;
        RECT  32.316 15.792 32.4 15.816 ;
    END
  END slots[91]
  PIN slots[92]
    DIRECTION OUTPUT ;
    USE SIGNAL ;
    PORT
      LAYER M4 ;
        RECT  32.316 15.888 32.4 15.912 ;
    END
  END slots[92]
  PIN slots[93]
    DIRECTION OUTPUT ;
    USE SIGNAL ;
    PORT
      LAYER M4 ;
        RECT  32.316 15.984 32.4 16.008 ;
    END
  END slots[93]
  PIN slots[94]
    DIRECTION OUTPUT ;
    USE SIGNAL ;
    PORT
      LAYER M4 ;
        RECT  32.316 3.792 32.4 3.816 ;
    END
  END slots[94]
  PIN slots[95]
    DIRECTION OUTPUT ;
    USE SIGNAL ;
    PORT
      LAYER M4 ;
        RECT  32.316 3.888 32.4 3.912 ;
    END
  END slots[95]
  PIN slots[96]
    DIRECTION OUTPUT ;
    USE SIGNAL ;
    PORT
      LAYER M4 ;
        RECT  32.316 3.984 32.4 4.008 ;
    END
  END slots[96]
  PIN slots[97]
    DIRECTION OUTPUT ;
    USE SIGNAL ;
    PORT
      LAYER M4 ;
        RECT  32.316 4.08 32.4 4.104 ;
    END
  END slots[97]
  PIN slots[98]
    DIRECTION OUTPUT ;
    USE SIGNAL ;
    PORT
      LAYER M4 ;
        RECT  32.316 4.176 32.4 4.2 ;
    END
  END slots[98]
  PIN slots[99]
    DIRECTION OUTPUT ;
    USE SIGNAL ;
    PORT
      LAYER M4 ;
        RECT  32.316 4.272 32.4 4.296 ;
    END
  END slots[99]
  PIN slots[9]
    DIRECTION OUTPUT ;
    USE SIGNAL ;
    PORT
      LAYER M4 ;
        RECT  32.316 20.976 32.4 21 ;
    END
  END slots[9]
  PIN write_next[0]
    DIRECTION INPUT ;
    USE SIGNAL ;
    PORT
      LAYER M4 ;
        RECT  0 16.176 0.084 16.2 ;
    END
  END write_next[0]
  PIN write_next[1]
    DIRECTION INPUT ;
    USE SIGNAL ;
    PORT
      LAYER M4 ;
        RECT  0 16.272 0.084 16.296 ;
    END
  END write_next[1]
  PIN VDD
    DIRECTION INOUT ;
    USE POWER ;
    PORT
      LAYER M5 ;
        RECT  29.592 2.151 29.712 30.249 ;
        RECT  26.892 2.151 27.012 30.249 ;
        RECT  24.192 2.151 24.312 30.249 ;
        RECT  21.492 2.151 21.612 30.249 ;
        RECT  18.792 2.151 18.912 30.249 ;
        RECT  16.092 2.151 16.212 30.249 ;
        RECT  13.392 2.151 13.512 30.249 ;
        RECT  10.692 2.151 10.812 30.249 ;
        RECT  7.992 2.151 8.112 30.249 ;
        RECT  5.292 2.151 5.412 30.249 ;
        RECT  2.592 2.151 2.712 30.249 ;
    END
  END VDD
  PIN VSS
    DIRECTION INOUT ;
    USE GROUND ;
    PORT
      LAYER M5 ;
        RECT  29.4 2.137 29.52 30.263 ;
        RECT  26.7 2.137 26.82 30.263 ;
        RECT  24 2.137 24.12 30.263 ;
        RECT  21.3 2.137 21.42 30.263 ;
        RECT  18.6 2.137 18.72 30.263 ;
        RECT  15.9 2.137 16.02 30.263 ;
        RECT  13.2 2.137 13.32 30.263 ;
        RECT  10.5 2.137 10.62 30.263 ;
        RECT  7.8 2.137 7.92 30.263 ;
        RECT  5.1 2.137 5.22 30.263 ;
        RECT  2.4 2.137 2.52 30.263 ;
    END
  END VSS
  # OT_OBS_CLOSED layer=M5 d_um=1.536 added=33
  OBS
    LAYER RVTN ;
     RECT  2.16 2.16 30.24 2.295 ;
     RECT  2.16 2.565 30.24 2.835 ;
     RECT  2.16 3.105 30.24 3.375 ;
     RECT  2.16 3.645 30.24 3.915 ;
     RECT  2.16 4.185 30.24 4.455 ;
     RECT  2.16 4.725 30.24 4.995 ;
     RECT  2.16 5.265 30.24 5.535 ;
     RECT  2.16 5.805 30.24 6.075 ;
     RECT  2.16 6.345 30.24 6.615 ;
     RECT  2.16 6.885 30.24 7.155 ;
     RECT  2.16 7.425 30.24 7.695 ;
     RECT  2.16 7.965 30.24 8.235 ;
     RECT  2.16 8.505 30.24 8.775 ;
     RECT  2.16 9.045 30.24 9.315 ;
     RECT  2.16 9.585 30.24 9.855 ;
     RECT  2.16 10.125 30.24 10.395 ;
     RECT  2.16 10.665 30.24 10.935 ;
     RECT  2.16 11.205 30.24 11.475 ;
     RECT  2.16 11.745 30.24 12.015 ;
     RECT  2.16 12.285 30.24 12.555 ;
     RECT  2.16 12.825 30.24 13.095 ;
     RECT  2.16 13.365 30.24 13.635 ;
     RECT  2.16 13.905 30.24 14.175 ;
     RECT  2.16 14.445 30.24 14.715 ;
     RECT  2.16 14.985 30.24 15.255 ;
     RECT  2.16 15.525 30.24 15.795 ;
     RECT  2.16 16.065 30.24 16.335 ;
     RECT  2.16 16.605 30.24 16.875 ;
     RECT  2.16 17.145 30.24 17.415 ;
     RECT  2.16 17.685 30.24 17.955 ;
     RECT  2.16 18.225 30.24 18.495 ;
     RECT  2.16 18.765 30.24 19.035 ;
     RECT  2.16 19.305 30.24 19.575 ;
     RECT  2.16 19.845 30.24 20.115 ;
     RECT  2.16 20.385 30.24 20.655 ;
     RECT  2.16 20.925 30.24 21.195 ;
     RECT  2.16 21.465 30.24 21.735 ;
     RECT  2.16 22.005 30.24 22.275 ;
     RECT  2.16 22.545 30.24 22.815 ;
     RECT  2.16 23.085 30.24 23.355 ;
     RECT  2.16 23.625 30.24 23.895 ;
     RECT  2.16 24.165 30.24 24.435 ;
     RECT  2.16 24.705 30.24 24.975 ;
     RECT  2.16 25.245 30.24 25.515 ;
     RECT  2.16 25.785 30.24 26.055 ;
     RECT  2.16 26.325 30.24 26.595 ;
     RECT  2.16 26.865 30.24 27.135 ;
     RECT  2.16 27.405 30.24 27.675 ;
     RECT  2.16 27.945 30.24 28.215 ;
     RECT  2.16 28.485 30.24 28.755 ;
     RECT  2.16 29.025 30.24 29.295 ;
     RECT  2.16 29.565 30.24 29.835 ;
     RECT  2.16 30.105 30.24 30.24 ;
    LAYER RVTP ;
     RECT  2.16 2.295 30.24 2.565 ;
     RECT  2.16 2.835 30.24 3.105 ;
     RECT  2.16 3.375 30.24 3.645 ;
     RECT  2.16 3.915 30.24 4.185 ;
     RECT  2.16 4.455 30.24 4.725 ;
     RECT  2.16 4.995 30.24 5.265 ;
     RECT  2.16 5.535 30.24 5.805 ;
     RECT  2.16 6.075 30.24 6.345 ;
     RECT  2.16 6.615 30.24 6.885 ;
     RECT  2.16 7.155 30.24 7.425 ;
     RECT  2.16 7.695 30.24 7.965 ;
     RECT  2.16 8.235 30.24 8.505 ;
     RECT  2.16 8.775 30.24 9.045 ;
     RECT  2.16 9.315 30.24 9.585 ;
     RECT  2.16 9.855 30.24 10.125 ;
     RECT  2.16 10.395 30.24 10.665 ;
     RECT  2.16 10.935 30.24 11.205 ;
     RECT  2.16 11.475 30.24 11.745 ;
     RECT  2.16 12.015 30.24 12.285 ;
     RECT  2.16 12.555 30.24 12.825 ;
     RECT  2.16 13.095 30.24 13.365 ;
     RECT  2.16 13.635 30.24 13.905 ;
     RECT  2.16 14.175 30.24 14.445 ;
     RECT  2.16 14.715 30.24 14.985 ;
     RECT  2.16 15.255 30.24 15.525 ;
     RECT  2.16 15.795 30.24 16.065 ;
     RECT  2.16 16.335 30.24 16.605 ;
     RECT  2.16 16.875 30.24 17.145 ;
     RECT  2.16 17.415 30.24 17.685 ;
     RECT  2.16 17.955 30.24 18.225 ;
     RECT  2.16 18.495 30.24 18.765 ;
     RECT  2.16 19.035 30.24 19.305 ;
     RECT  2.16 19.575 30.24 19.845 ;
     RECT  2.16 20.115 30.24 20.385 ;
     RECT  2.16 20.655 30.24 20.925 ;
     RECT  2.16 21.195 30.24 21.465 ;
     RECT  2.16 21.735 30.24 22.005 ;
     RECT  2.16 22.275 30.24 22.545 ;
     RECT  2.16 22.815 30.24 23.085 ;
     RECT  2.16 23.355 30.24 23.625 ;
     RECT  2.16 23.895 30.24 24.165 ;
     RECT  2.16 24.435 30.24 24.705 ;
     RECT  2.16 24.975 30.24 25.245 ;
     RECT  2.16 25.515 30.24 25.785 ;
     RECT  2.16 26.055 30.24 26.325 ;
     RECT  2.16 26.595 30.24 26.865 ;
     RECT  2.16 27.135 30.24 27.405 ;
     RECT  2.16 27.675 30.24 27.945 ;
     RECT  2.16 28.215 30.24 28.485 ;
     RECT  2.16 28.755 30.24 29.025 ;
     RECT  2.16 29.295 30.24 29.565 ;
     RECT  2.16 29.835 30.24 30.105 ;
    LAYER M1 ;
     RECT  2.16 2.151 30.24 30.249 ;
    LAYER M2 ;
     RECT  0.031 18.432 0.103 18.45 ;
     RECT  0.031 21.906 0.103 21.924 ;
     RECT  0.103 8.208 0.139 9.459 ;
     RECT  0.103 21.744 0.139 21.924 ;
     RECT  0.139 8.208 0.175 10.116 ;
     RECT  0.139 10.872 0.175 10.89 ;
     RECT  0.175 8.208 0.203 10.89 ;
     RECT  0.103 16.848 0.203 18.45 ;
     RECT  0.203 8.586 0.211 10.89 ;
     RECT  0.203 18.432 0.211 18.45 ;
     RECT  0.103 19.206 0.211 19.224 ;
     RECT  0.139 21.546 0.239 21.924 ;
     RECT  0.211 18.432 0.311 19.224 ;
     RECT  0.211 8.586 0.347 11.124 ;
     RECT  0.239 21.816 0.419 21.924 ;
     RECT  0.391 5.202 0.427 5.22 ;
     RECT  0.427 5.202 0.463 5.796 ;
     RECT  0.311 19.206 0.499 19.224 ;
     RECT  0.203 17.586 2.011 17.604 ;
     RECT  0.311 18.432 2.011 18.45 ;
     RECT  0.463 5.202 2.16 6.03 ;
     RECT  0.347 8.586 2.16 9.144 ;
     RECT  0.347 9.936 2.16 11.124 ;
     RECT  0.175 12.294 2.16 12.312 ;
     RECT  0.103 14.652 2.16 14.67 ;
     RECT  2.011 17.586 2.16 18.45 ;
     RECT  0.499 19.206 2.16 19.566 ;
     RECT  0.103 20.322 2.16 20.34 ;
     RECT  0.535 22.014 2.16 22.032 ;
     RECT  2.16 2.151 24.439 30.249 ;
     RECT  24.439 1.962 25.987 30.249 ;
     RECT  25.987 1.881 28.247 30.249 ;
     RECT  28.247 1.962 29.579 30.249 ;
     RECT  29.579 2.151 30.24 30.249 ;
     RECT  30.24 2.574 30.839 30.132 ;
     RECT  30.839 4.806 30.911 30.132 ;
     RECT  30.911 5.85 31.019 30.132 ;
     RECT  30.839 2.574 31.055 3.978 ;
     RECT  31.019 10.368 31.235 30.132 ;
     RECT  31.235 10.368 31.271 29.016 ;
     RECT  31.271 10.368 31.307 26.892 ;
     RECT  31.271 28.116 31.307 29.016 ;
     RECT  31.235 30.006 31.307 30.132 ;
     RECT  31.307 10.368 31.343 14.436 ;
     RECT  31.307 15.57 31.343 19.224 ;
     RECT  31.307 20.016 31.343 25.272 ;
     RECT  31.307 26.298 31.343 26.892 ;
     RECT  31.307 28.296 31.343 29.016 ;
     RECT  31.307 30.078 31.343 30.132 ;
     RECT  31.055 3.006 31.379 3.978 ;
     RECT  30.911 4.806 31.379 5.022 ;
     RECT  31.019 5.85 31.379 9.576 ;
     RECT  31.343 10.368 31.379 10.854 ;
     RECT  31.343 13.068 31.379 14.436 ;
     RECT  31.343 15.84 31.379 16.524 ;
     RECT  31.343 17.658 31.379 18.828 ;
     RECT  31.343 20.016 31.379 20.376 ;
     RECT  31.343 21.402 31.379 22.23 ;
     RECT  31.343 23.328 31.379 23.85 ;
     RECT  31.379 3.276 31.415 3.978 ;
     RECT  31.379 5.85 31.415 8.424 ;
     RECT  31.379 16.236 31.415 16.524 ;
     RECT  31.379 21.402 31.415 22.104 ;
     RECT  31.415 3.276 31.451 3.834 ;
     RECT  31.415 8.406 31.451 8.424 ;
     RECT  31.379 23.796 31.451 23.814 ;
     RECT  31.451 3.816 31.487 3.834 ;
     RECT  31.415 16.272 31.487 16.524 ;
     RECT  31.379 9.216 32.215 9.576 ;
     RECT  31.415 6.048 32.243 7.524 ;
     RECT  31.343 24.606 32.243 25.272 ;
     RECT  31.379 4.896 32.279 5.022 ;
     RECT  32.243 6.246 32.279 7.524 ;
     RECT  32.215 8.586 32.279 9.576 ;
     RECT  31.379 13.68 32.279 13.734 ;
     RECT  31.379 17.658 32.279 18.252 ;
     RECT  31.379 20.052 32.279 20.106 ;
     RECT  31.415 21.402 32.279 21.834 ;
     RECT  31.343 28.53 32.279 29.016 ;
     RECT  32.279 5.004 32.315 5.022 ;
     RECT  32.279 6.786 32.315 7.524 ;
     RECT  32.279 8.586 32.315 8.604 ;
     RECT  32.279 9.396 32.315 9.576 ;
     RECT  31.379 10.368 32.315 10.62 ;
     RECT  31.343 11.826 32.315 11.844 ;
     RECT  32.279 13.68 32.315 13.698 ;
     RECT  31.487 16.506 32.315 16.524 ;
     RECT  32.279 17.766 32.315 18.252 ;
     RECT  32.279 20.088 32.315 20.106 ;
     RECT  32.279 21.438 32.315 21.726 ;
     RECT  32.243 24.606 32.315 24.624 ;
     RECT  31.343 26.496 32.315 26.892 ;
     RECT  31.343 30.114 32.315 30.132 ;
    LAYER M3 ;
     RECT  25.992 1.876 26.442 2.029 ;
     RECT  29.556 1.957 29.574 2.029 ;
     RECT  25.992 2.029 27.126 2.065 ;
     RECT  25.992 2.065 27.342 2.101 ;
     RECT  28.224 1.876 28.242 2.101 ;
     RECT  24.444 1.957 24.462 2.143 ;
     RECT  24.015 2.143 24.462 2.191 ;
     RECT  25.992 2.101 28.242 2.191 ;
     RECT  29.124 2.029 29.574 2.191 ;
     RECT  23.904 2.191 24.462 2.227 ;
     RECT  23.832 2.227 24.462 2.251 ;
     RECT  25.2 2.101 25.218 2.251 ;
     RECT  23.832 2.251 25.218 2.347 ;
     RECT  25.992 2.191 29.574 2.347 ;
     RECT  23.832 2.347 29.574 2.371 ;
     RECT  2.415 2.143 2.505 2.413 ;
     RECT  5.115 2.143 5.205 2.413 ;
     RECT  7.815 2.143 7.905 2.413 ;
     RECT  10.515 2.143 10.605 2.413 ;
     RECT  13.215 2.143 13.305 2.413 ;
     RECT  15.915 2.143 16.005 2.413 ;
     RECT  18.615 2.143 18.705 2.413 ;
     RECT  21.315 2.143 21.405 2.413 ;
     RECT  23.832 2.371 29.79 2.461 ;
     RECT  23.832 2.461 29.862 2.491 ;
     RECT  18.615 2.413 18.897 2.569 ;
     RECT  23.58 2.491 29.862 2.641 ;
     RECT  22.464 2.371 22.482 2.767 ;
     RECT  22.392 2.767 22.482 2.911 ;
     RECT  23.58 2.641 29.934 2.911 ;
     RECT  22.392 2.911 29.934 3.001 ;
     RECT  31.032 2.569 31.05 3.001 ;
     RECT  22.392 3.001 30.078 3.181 ;
     RECT  21.315 2.413 21.597 3.271 ;
     RECT  22.392 3.181 30.114 3.271 ;
     RECT  31.032 3.001 31.374 3.271 ;
     RECT  10.515 2.413 10.797 3.307 ;
     RECT  21.315 3.271 30.114 3.307 ;
     RECT  20.484 3.451 20.502 3.541 ;
     RECT  21.315 3.307 30.186 3.541 ;
     RECT  10.515 3.307 11.25 3.721 ;
     RECT  31.032 3.271 31.446 3.811 ;
     RECT  20.484 3.541 30.186 3.883 ;
     RECT  31.032 3.811 31.482 3.883 ;
     RECT  18.615 2.569 19.026 3.919 ;
     RECT  20.484 3.883 31.482 4.205 ;
     RECT  20.484 4.205 31.446 4.351 ;
     RECT  17.82 2.803 17.838 4.387 ;
     RECT  18.576 3.919 19.026 4.531 ;
     RECT  19.764 4.351 31.446 4.531 ;
     RECT  15.915 2.413 16.197 4.621 ;
     RECT  32.256 4.267 32.274 4.651 ;
     RECT  15.915 4.621 16.362 4.693 ;
     RECT  15.915 4.693 16.398 4.765 ;
     RECT  14.832 4.729 14.85 4.801 ;
     RECT  15.915 4.765 16.758 4.891 ;
     RECT  17.64 4.387 17.838 4.891 ;
     RECT  32.256 4.651 32.31 4.919 ;
     RECT  13.215 2.413 13.497 4.927 ;
     RECT  32.292 4.919 32.31 5.027 ;
     RECT  14.832 4.801 14.886 5.071 ;
     RECT  15.915 4.891 17.838 5.071 ;
     RECT  14.832 5.071 17.838 5.161 ;
     RECT  18.576 4.531 31.446 5.161 ;
     RECT  10.515 3.721 11.43 5.459 ;
     RECT  0.396 5.197 0.414 5.467 ;
     RECT  12.42 4.963 12.438 5.503 ;
     RECT  13.176 4.927 13.497 5.503 ;
     RECT  14.832 5.161 31.446 5.531 ;
     RECT  10.515 5.459 10.926 5.873 ;
     RECT  12.42 5.503 13.497 5.999 ;
     RECT  15.408 5.531 31.446 6.107 ;
     RECT  18.468 6.107 31.446 6.115 ;
     RECT  18.468 6.115 31.482 6.196 ;
     RECT  32.22 6.043 32.238 6.196 ;
     RECT  18.468 6.196 32.238 6.241 ;
     RECT  15.408 6.107 17.73 6.283 ;
     RECT  18.468 6.241 32.274 6.449 ;
     RECT  11.844 6.421 11.862 6.539 ;
     RECT  15.264 6.283 17.73 6.583 ;
     RECT  30.744 6.449 32.274 6.605 ;
     RECT  31.428 6.605 32.274 6.667 ;
     RECT  5.115 2.413 5.397 6.691 ;
     RECT  6.84 6.583 6.858 6.781 ;
     RECT  7.815 2.413 8.097 6.781 ;
     RECT  14.868 6.583 17.73 6.781 ;
     RECT  0.396 5.467 0.558 6.797 ;
     RECT  5.115 6.691 6.066 6.809 ;
     RECT  31.428 6.667 32.31 6.845 ;
     RECT  9.576 6.655 9.594 6.925 ;
     RECT  2.415 2.413 2.697 6.952 ;
     RECT  5.115 6.809 5.397 6.952 ;
     RECT  14.652 6.781 17.73 6.961 ;
     RECT  18.468 6.449 29.934 6.961 ;
     RECT  9.288 6.925 9.594 7.079 ;
     RECT  5.004 6.952 5.397 7.088 ;
     RECT  10.515 5.873 10.797 7.123 ;
     RECT  9.288 7.079 9.378 7.133 ;
     RECT  9.288 7.133 9.306 7.147 ;
     RECT  32.22 6.845 32.31 7.181 ;
     RECT  14.652 6.961 29.934 7.195 ;
     RECT  9.108 7.147 9.306 7.223 ;
     RECT  13.215 5.999 13.497 7.231 ;
     RECT  14.292 7.195 29.934 7.231 ;
     RECT  13.215 7.231 29.934 7.339 ;
     RECT  13.215 7.339 30.186 7.393 ;
     RECT  0.144 7.243 0.162 7.421 ;
     RECT  12.564 7.393 30.186 7.435 ;
     RECT  10.515 7.123 10.854 7.465 ;
     RECT  2.304 6.952 2.697 7.483 ;
     RECT  32.292 7.181 32.31 7.529 ;
     RECT  5.115 7.088 5.397 7.531 ;
     RECT  31.428 6.845 31.446 7.565 ;
     RECT  5.115 7.531 5.598 7.619 ;
     RECT  6.84 6.781 8.097 7.663 ;
     RECT  2.304 7.483 2.97 7.675 ;
     RECT  10.515 7.465 10.89 7.699 ;
     RECT  3.996 6.817 4.014 7.763 ;
     RECT  11.952 7.435 30.186 7.771 ;
     RECT  31.356 7.735 31.41 7.771 ;
     RECT  6.84 7.663 8.73 7.889 ;
     RECT  11.952 7.771 31.41 7.889 ;
     RECT  2.304 7.675 3.042 7.901 ;
     RECT  10.515 7.699 10.926 7.915 ;
     RECT  6.84 7.889 7.074 7.925 ;
     RECT  10.116 7.915 10.926 7.961 ;
     RECT  14.22 7.889 31.41 7.961 ;
     RECT  7.815 7.889 8.73 8.041 ;
     RECT  7.815 8.041 9.594 8.159 ;
     RECT  14.796 7.961 31.41 8.159 ;
     RECT  7.815 8.159 8.514 8.195 ;
     RECT  10.515 7.961 10.926 8.203 ;
     RECT  10.515 8.203 11.106 8.24 ;
     RECT  5.115 7.619 5.49 8.339 ;
     RECT  14.832 8.159 31.41 8.401 ;
     RECT  32.148 8.299 32.166 8.401 ;
     RECT  11.952 7.889 13.497 8.437 ;
     RECT  9.36 8.159 9.594 8.477 ;
     RECT  11.736 8.437 13.497 8.477 ;
     RECT  14.832 8.401 32.166 8.525 ;
     RECT  15.408 8.525 32.166 8.537 ;
     RECT  18.252 8.537 32.166 8.539 ;
     RECT  18.252 8.539 32.238 8.581 ;
     RECT  18.252 8.581 32.31 8.621 ;
     RECT  5.115 8.339 5.397 8.671 ;
     RECT  11.88 8.477 13.497 8.699 ;
     RECT  2.304 7.901 2.697 8.717 ;
     RECT  5.004 8.671 5.397 8.717 ;
     RECT  15.408 8.537 17.406 8.735 ;
     RECT  11.916 8.699 13.497 8.861 ;
     RECT  11.916 8.861 12.15 9.005 ;
     RECT  10.515 8.24 10.998 9.013 ;
     RECT  9.9 9.013 10.998 9.053 ;
     RECT  10.515 9.053 10.998 9.121 ;
     RECT  0.108 8.188 0.198 9.163 ;
     RECT  9.036 9.085 9.054 9.239 ;
     RECT  2.415 8.717 2.697 9.259 ;
     RECT  10.515 9.121 11.07 9.275 ;
     RECT  8.82 9.247 8.838 9.293 ;
     RECT  18.252 8.621 32.274 9.293 ;
     RECT  32.112 9.293 32.274 9.355 ;
     RECT  0.108 9.163 0.342 9.389 ;
     RECT  2.415 9.259 2.718 9.389 ;
     RECT  6.84 7.925 6.966 9.389 ;
     RECT  7.815 8.195 8.097 9.391 ;
     RECT  7.815 9.391 8.298 9.509 ;
     RECT  6.948 9.389 6.966 9.517 ;
     RECT  7.815 9.509 8.097 9.517 ;
     RECT  15.516 8.735 17.406 9.517 ;
     RECT  18.252 9.293 31.374 9.533 ;
     RECT  20.52 9.533 31.374 9.545 ;
     RECT  32.112 9.355 32.31 9.581 ;
     RECT  11.988 9.005 12.15 9.625 ;
     RECT  13.215 8.861 13.497 9.625 ;
     RECT  15.408 9.517 17.406 9.625 ;
     RECT  2.415 9.389 2.697 9.643 ;
     RECT  5.115 8.717 5.397 9.643 ;
     RECT  6.948 9.517 8.097 9.677 ;
     RECT  11.988 9.625 13.497 9.677 ;
     RECT  32.112 9.581 32.274 9.677 ;
     RECT  5.004 9.643 5.397 9.689 ;
     RECT  20.664 9.545 31.374 9.773 ;
     RECT  11.988 9.677 12.15 9.787 ;
     RECT  0.108 9.389 0.234 9.968 ;
     RECT  5.115 9.689 5.397 10.021 ;
     RECT  5.115 10.021 5.49 10.061 ;
     RECT  14.868 9.625 17.406 10.085 ;
     RECT  6.948 9.677 6.966 10.123 ;
     RECT  10.515 9.275 10.818 10.129 ;
     RECT  11.592 9.787 12.15 10.129 ;
     RECT  6.84 10.123 6.966 10.157 ;
     RECT  9.756 9.355 9.774 10.219 ;
     RECT  10.515 10.129 12.15 10.219 ;
     RECT  2.304 9.643 2.697 10.253 ;
     RECT  7.704 9.677 8.097 10.253 ;
     RECT  14.976 10.085 17.406 10.291 ;
     RECT  18.252 9.533 19.422 10.291 ;
     RECT  9.756 10.219 12.15 10.315 ;
     RECT  32.256 9.677 32.274 10.315 ;
     RECT  14.976 10.291 19.422 10.327 ;
     RECT  14.976 10.327 19.602 10.363 ;
     RECT  20.664 9.773 29.97 10.363 ;
     RECT  32.256 10.315 32.31 10.471 ;
     RECT  30.744 9.773 31.374 10.507 ;
     RECT  9.684 10.315 12.15 10.637 ;
     RECT  0.108 9.968 0.162 10.699 ;
     RECT  13.215 9.677 13.497 10.741 ;
     RECT  0.108 10.699 0.198 10.795 ;
     RECT  9.684 10.637 11.106 10.831 ;
     RECT  9.144 10.831 11.106 10.973 ;
     RECT  13.215 10.741 13.986 11.011 ;
     RECT  14.976 10.363 29.97 11.011 ;
     RECT  2.415 10.253 2.697 11.083 ;
     RECT  0.108 10.795 0.234 11.129 ;
     RECT  9.144 10.973 10.89 11.165 ;
     RECT  30.708 10.507 31.374 11.201 ;
     RECT  13.215 11.011 29.97 11.227 ;
     RECT  6.84 10.157 6.93 11.245 ;
     RECT  7.815 10.253 8.097 11.245 ;
     RECT  2.376 11.083 2.697 11.272 ;
     RECT  5.115 10.061 5.397 11.272 ;
     RECT  13.215 11.227 30.006 11.273 ;
     RECT  5.004 11.272 5.397 11.309 ;
     RECT  9.756 11.165 10.89 11.435 ;
     RECT  32.184 10.471 32.31 11.501 ;
     RECT  6.84 11.245 8.097 11.659 ;
     RECT  8.82 11.551 8.838 11.659 ;
     RECT  6.84 11.659 8.838 11.677 ;
     RECT  31.212 11.201 31.374 11.693 ;
     RECT  2.304 11.272 2.697 11.707 ;
     RECT  13.215 11.273 29.97 11.707 ;
     RECT  12.132 10.637 12.15 11.755 ;
     RECT  13.104 11.707 29.97 11.755 ;
     RECT  2.304 11.707 2.862 11.803 ;
     RECT  2.304 11.803 2.97 11.885 ;
     RECT  6.48 11.677 8.838 11.939 ;
     RECT  3.996 11.371 4.014 11.975 ;
     RECT  6.552 11.939 8.838 11.975 ;
     RECT  2.376 11.885 2.97 11.981 ;
     RECT  32.292 11.501 32.31 11.981 ;
     RECT  6.84 11.975 8.838 11.984 ;
     RECT  10.515 11.435 10.89 12.019 ;
     RECT  6.876 11.984 8.838 12.043 ;
     RECT  9.756 11.435 9.774 12.043 ;
     RECT  2.376 11.981 2.862 12.047 ;
     RECT  10.515 12.019 10.926 12.055 ;
     RECT  12.132 11.755 29.97 12.091 ;
     RECT  6.876 12.043 9.774 12.181 ;
     RECT  10.515 12.055 10.998 12.181 ;
     RECT  12.132 12.091 30.114 12.235 ;
     RECT  31.212 11.693 31.338 12.235 ;
     RECT  6.876 12.181 10.998 12.245 ;
     RECT  0.108 11.129 0.126 12.289 ;
     RECT  2.415 12.047 2.862 12.317 ;
     RECT  9.468 12.245 10.998 12.389 ;
     RECT  0.108 12.289 0.198 12.461 ;
     RECT  6.876 12.245 8.19 12.479 ;
     RECT  6.876 12.479 6.894 12.515 ;
     RECT  7.704 12.479 8.097 12.515 ;
     RECT  9.468 12.389 10.854 12.515 ;
     RECT  12.132 12.235 31.338 12.515 ;
     RECT  9.864 12.515 10.854 12.551 ;
     RECT  12.132 12.515 12.438 12.785 ;
     RECT  10.515 12.551 10.854 12.929 ;
     RECT  13.215 12.515 31.338 13.063 ;
     RECT  13.215 13.063 31.374 13.559 ;
     RECT  32.292 13.483 32.31 13.579 ;
     RECT  32.256 13.579 32.31 13.703 ;
     RECT  13.215 13.559 29.898 13.709 ;
     RECT  32.256 13.703 32.274 13.739 ;
     RECT  14.256 13.709 29.898 13.865 ;
     RECT  14.4 13.865 29.898 13.901 ;
     RECT  14.4 13.901 29.826 14.237 ;
     RECT  30.78 13.559 31.374 14.413 ;
     RECT  7.815 12.515 8.097 14.485 ;
     RECT  30.672 14.413 31.374 14.573 ;
     RECT  14.472 14.237 29.826 14.635 ;
     RECT  30.672 14.573 31.302 14.635 ;
     RECT  0.108 12.461 0.126 14.675 ;
     RECT  7.815 14.485 8.298 14.909 ;
     RECT  14.472 14.635 31.302 14.945 ;
     RECT  19.98 14.945 31.302 15.053 ;
     RECT  14.472 14.945 18.897 15.323 ;
     RECT  12.132 12.785 12.15 15.331 ;
     RECT  12.132 15.331 12.294 15.421 ;
     RECT  20.376 15.053 31.302 15.499 ;
     RECT  20.376 15.499 31.338 15.719 ;
     RECT  14.832 15.323 18.897 15.773 ;
     RECT  5.115 11.309 5.397 15.799 ;
     RECT  13.215 13.709 13.497 15.829 ;
     RECT  13.104 15.829 13.497 15.835 ;
     RECT  20.772 15.719 31.338 15.835 ;
     RECT  12.024 15.421 12.294 15.871 ;
     RECT  13.104 15.835 13.734 15.871 ;
     RECT  19.836 15.787 20.034 15.961 ;
     RECT  2.415 12.317 2.697 15.979 ;
     RECT  4.644 15.799 5.397 15.989 ;
     RECT  2.304 15.979 2.697 15.997 ;
     RECT  17.1 15.773 18.897 15.997 ;
     RECT  19.692 15.961 20.034 15.997 ;
     RECT  2.304 15.997 3.186 16.033 ;
     RECT  7.815 14.909 8.226 16.105 ;
     RECT  12.024 15.871 13.734 16.105 ;
     RECT  14.832 15.773 15.138 16.105 ;
     RECT  2.304 16.033 3.258 16.141 ;
     RECT  10.515 12.929 10.797 16.141 ;
     RECT  4.104 16.069 4.122 16.169 ;
     RECT  2.304 16.141 3.366 16.171 ;
     RECT  2.268 16.171 3.366 16.231 ;
     RECT  7.776 16.105 8.226 16.231 ;
     RECT  20.772 15.835 31.374 16.231 ;
     RECT  12.024 16.105 15.138 16.259 ;
     RECT  7.596 16.231 8.226 16.267 ;
     RECT  20.772 16.231 31.41 16.267 ;
     RECT  2.268 16.231 4.05 16.295 ;
     RECT  10.515 16.141 10.926 16.295 ;
     RECT  14.544 16.259 15.138 16.295 ;
     RECT  6.768 16.231 6.786 16.303 ;
     RECT  7.596 16.267 8.73 16.303 ;
     RECT  10.515 16.295 10.797 16.339 ;
     RECT  12.024 16.259 13.806 16.501 ;
     RECT  17.1 15.997 20.034 16.507 ;
     RECT  20.772 16.267 31.482 16.507 ;
     RECT  2.304 16.295 4.05 16.529 ;
     RECT  10.512 16.339 10.797 16.529 ;
     RECT  6.768 16.303 8.73 16.541 ;
     RECT  11.88 16.501 13.806 16.565 ;
     RECT  11.88 16.565 11.898 16.637 ;
     RECT  17.1 16.507 31.482 16.645 ;
     RECT  6.948 16.541 8.73 16.651 ;
     RECT  14.832 16.295 15.138 16.771 ;
     RECT  15.915 15.773 16.197 16.771 ;
     RECT  17.028 16.645 31.482 16.771 ;
     RECT  0.108 16.747 0.126 16.795 ;
     RECT  2.304 16.529 3.258 16.799 ;
     RECT  14.832 16.771 15.174 16.807 ;
     RECT  15.915 16.771 31.482 16.807 ;
     RECT  3.996 16.529 4.05 16.939 ;
     RECT  6.948 16.651 9.054 16.951 ;
     RECT  6.948 16.951 9.27 17.069 ;
     RECT  3.996 16.939 4.086 17.077 ;
     RECT  14.832 16.807 31.482 17.077 ;
     RECT  6.948 17.069 9.054 17.105 ;
     RECT  3.996 17.077 4.302 17.117 ;
     RECT  14.724 17.077 31.482 17.165 ;
     RECT  0.108 16.795 0.198 17.213 ;
     RECT  13.215 16.565 13.806 17.311 ;
     RECT  14.724 17.165 31.338 17.311 ;
     RECT  6.948 17.105 8.73 17.383 ;
     RECT  13.215 17.311 31.338 17.383 ;
     RECT  6.912 17.383 8.73 17.419 ;
     RECT  10.515 16.529 10.797 17.419 ;
     RECT  13.14 17.383 31.338 17.419 ;
     RECT  10.515 17.419 10.854 17.491 ;
     RECT  32.292 15.979 32.31 17.515 ;
     RECT  12.816 17.419 31.338 17.519 ;
     RECT  6.66 17.419 8.73 17.609 ;
     RECT  12.816 17.519 30.006 17.645 ;
     RECT  32.256 17.515 32.31 17.681 ;
     RECT  3.996 17.117 4.086 17.717 ;
     RECT  2.304 16.799 2.97 17.851 ;
     RECT  6.912 17.609 8.73 17.879 ;
     RECT  13.14 17.645 30.006 17.915 ;
     RECT  7.056 17.879 8.73 17.933 ;
     RECT  10.515 17.491 10.926 17.959 ;
     RECT  10.515 17.959 10.998 17.995 ;
     RECT  2.304 17.851 3.078 18.031 ;
     RECT  2.016 18.031 3.078 18.125 ;
     RECT  10.515 17.995 11.646 18.187 ;
     RECT  0.108 17.213 0.126 18.193 ;
     RECT  30.78 17.519 31.338 18.193 ;
     RECT  32.292 17.681 32.31 18.257 ;
     RECT  7.164 17.933 8.73 18.301 ;
     RECT  2.304 18.125 3.078 18.329 ;
     RECT  13.176 17.915 30.006 18.379 ;
     RECT  30.78 18.193 31.374 18.379 ;
     RECT  0.108 18.193 0.198 18.427 ;
     RECT  10.26 18.187 11.646 18.427 ;
     RECT  10.26 18.427 11.862 18.455 ;
     RECT  3.996 17.717 4.05 18.527 ;
     RECT  11.844 18.455 11.862 18.563 ;
     RECT  0.036 18.427 0.198 18.571 ;
     RECT  2.415 18.329 3.078 18.661 ;
     RECT  3.996 18.527 4.014 18.661 ;
     RECT  7.164 18.301 9.306 18.725 ;
     RECT  13.176 18.379 31.374 18.725 ;
     RECT  2.415 18.661 4.014 18.797 ;
     RECT  6.912 18.76 6.93 18.797 ;
     RECT  14.688 18.725 31.374 18.797 ;
     RECT  6.84 18.811 6.894 18.841 ;
     RECT  13.176 18.725 13.497 18.841 ;
     RECT  30.996 18.797 31.374 18.893 ;
     RECT  3.996 18.797 4.014 18.995 ;
     RECT  14.688 18.797 30.186 19.103 ;
     RECT  7.815 18.725 9.306 19.111 ;
     RECT  10.26 18.455 11.106 19.111 ;
     RECT  32.292 19.051 32.31 19.147 ;
     RECT  7.815 19.111 11.106 19.229 ;
     RECT  30.996 18.893 31.338 19.229 ;
     RECT  7.815 19.229 8.802 19.265 ;
     RECT  6.588 18.841 6.894 19.381 ;
     RECT  12.708 18.841 13.497 19.381 ;
     RECT  2.415 18.797 2.862 19.435 ;
     RECT  5.115 15.989 5.397 19.471 ;
     RECT  6.444 19.381 6.894 19.471 ;
     RECT  5.115 19.471 6.894 19.483 ;
     RECT  7.815 19.265 8.73 19.499 ;
     RECT  9.576 19.229 11.106 19.535 ;
     RECT  12.456 19.381 13.497 19.535 ;
     RECT  14.832 19.103 30.186 19.535 ;
     RECT  0.036 18.571 0.306 19.543 ;
     RECT  2.304 19.435 2.862 19.543 ;
     RECT  5.004 19.483 6.894 19.607 ;
     RECT  5.115 19.607 6.894 19.627 ;
     RECT  7.815 19.499 8.622 19.627 ;
     RECT  5.115 19.627 8.622 19.679 ;
     RECT  15.84 19.535 30.186 19.741 ;
     RECT  30.996 19.229 31.302 19.741 ;
     RECT  9.576 19.535 9.594 19.805 ;
     RECT  10.332 19.535 11.106 19.853 ;
     RECT  13.104 19.535 13.497 19.949 ;
     RECT  15.84 19.741 31.302 20.005 ;
     RECT  2.304 19.543 2.898 20.011 ;
     RECT  14.832 19.535 14.85 20.075 ;
     RECT  32.256 19.147 32.31 20.111 ;
     RECT  2.304 20.011 2.97 20.141 ;
     RECT  15.84 20.005 31.374 20.429 ;
     RECT  10.515 19.853 11.106 20.623 ;
     RECT  5.115 19.679 5.634 20.669 ;
     RECT  13.176 19.949 13.497 20.683 ;
     RECT  6.984 19.679 8.622 20.759 ;
     RECT  10.515 20.623 11.286 20.821 ;
     RECT  4.248 20.443 4.266 20.827 ;
     RECT  14.436 20.731 14.526 20.921 ;
     RECT  3.996 20.827 4.266 20.965 ;
     RECT  5.115 20.669 5.397 20.965 ;
     RECT  2.304 20.141 2.934 20.971 ;
     RECT  3.996 20.965 5.397 20.971 ;
     RECT  6.984 20.759 8.097 20.971 ;
     RECT  14.436 20.921 14.454 20.993 ;
     RECT  6.912 20.971 8.097 21.029 ;
     RECT  2.304 20.971 5.397 21.155 ;
     RECT  8.892 20.857 8.91 21.163 ;
     RECT  3.816 21.155 5.397 21.197 ;
     RECT  8.892 21.163 9.018 21.235 ;
     RECT  13.104 20.683 13.497 21.235 ;
     RECT  32.256 20.111 32.274 21.355 ;
     RECT  13.104 21.235 13.59 21.389 ;
     RECT  10.515 20.821 11.862 21.451 ;
     RECT  4.176 21.197 5.397 21.469 ;
     RECT  4.176 21.469 5.742 21.505 ;
     RECT  13.104 21.389 13.497 21.533 ;
     RECT  8.892 21.235 9.09 21.569 ;
     RECT  10.515 21.451 11.898 21.569 ;
     RECT  13.14 21.533 13.497 21.569 ;
     RECT  4.176 21.505 6.03 21.659 ;
     RECT  10.515 21.569 11.79 21.659 ;
     RECT  10.515 21.659 11.61 21.695 ;
     RECT  4.176 21.659 5.706 21.725 ;
     RECT  5.004 21.725 5.706 21.731 ;
     RECT  32.256 21.355 32.31 21.731 ;
     RECT  7.488 21.029 8.097 21.775 ;
     RECT  4.176 21.725 4.194 21.803 ;
     RECT  10.515 21.695 10.962 21.839 ;
     RECT  32.256 21.731 32.274 21.839 ;
     RECT  6.876 21.775 8.097 21.928 ;
     RECT  0.036 19.543 0.522 21.929 ;
     RECT  5.115 21.731 5.706 21.929 ;
     RECT  5.115 21.929 5.49 21.965 ;
     RECT  6.84 21.928 8.097 21.965 ;
     RECT  15.84 20.429 31.338 21.965 ;
     RECT  2.304 21.155 2.826 21.979 ;
     RECT  0.108 21.929 0.522 22.009 ;
     RECT  14.544 21.811 14.562 22.009 ;
     RECT  9.54 22.009 9.558 22.045 ;
     RECT  15.876 21.965 31.338 22.081 ;
     RECT  2.304 21.979 2.862 22.109 ;
     RECT  6.876 21.965 8.097 22.109 ;
     RECT  14.328 22.009 14.886 22.109 ;
     RECT  2.304 22.109 2.697 22.157 ;
     RECT  15.876 22.081 31.41 22.157 ;
     RECT  9.54 22.045 9.738 22.199 ;
     RECT  14.328 22.109 14.346 22.199 ;
     RECT  7.2 22.109 8.097 22.235 ;
     RECT  9.54 22.199 9.558 22.235 ;
     RECT  0.108 22.009 0.558 22.253 ;
     RECT  0.108 22.253 0.522 22.349 ;
     RECT  0.108 22.349 0.126 22.445 ;
     RECT  30.78 22.157 31.41 22.445 ;
     RECT  15.876 22.157 29.862 22.649 ;
     RECT  30.78 22.445 31.338 22.987 ;
     RECT  30.744 22.987 31.338 23.053 ;
     RECT  15.915 22.649 29.862 23.083 ;
     RECT  15.915 23.083 29.97 23.161 ;
     RECT  30.708 23.053 31.338 23.161 ;
     RECT  15.915 23.161 31.338 23.323 ;
     RECT  15.915 23.323 31.374 23.791 ;
     RECT  15.915 23.791 31.446 24.365 ;
     RECT  31.176 24.365 31.446 24.557 ;
     RECT  32.292 24.427 32.31 24.629 ;
     RECT  31.176 24.557 31.374 24.941 ;
     RECT  15.915 24.365 30.222 25.195 ;
     RECT  31.176 24.941 31.338 25.195 ;
     RECT  32.22 25.249 32.238 25.325 ;
     RECT  15.915 25.195 31.338 26.249 ;
     RECT  17.676 26.249 31.338 26.393 ;
     RECT  17.712 26.393 31.338 26.539 ;
     RECT  17.712 26.539 31.374 26.663 ;
     RECT  17.712 26.663 31.338 26.789 ;
     RECT  17.712 26.789 19.602 27.715 ;
     RECT  20.52 26.789 31.338 27.715 ;
     RECT  15.915 26.249 16.794 27.743 ;
     RECT  17.712 27.715 31.338 27.841 ;
     RECT  17.64 27.841 31.338 28.139 ;
     RECT  32.292 26.155 32.31 28.171 ;
     RECT  17.64 28.139 17.658 28.175 ;
     RECT  18.576 28.139 31.338 28.267 ;
     RECT  18.576 28.267 31.41 28.363 ;
     RECT  32.256 28.171 32.31 28.363 ;
     RECT  18.576 28.363 32.31 28.397 ;
     RECT  32.112 28.397 32.31 28.493 ;
     RECT  18.576 28.397 31.338 28.859 ;
     RECT  18.615 28.859 31.338 28.973 ;
     RECT  32.256 28.493 32.31 29.021 ;
     RECT  18.615 28.973 29.898 29.219 ;
     RECT  30.672 28.973 31.338 29.219 ;
     RECT  18.615 29.219 18.954 29.255 ;
     RECT  20.304 29.219 29.898 29.489 ;
     RECT  21.315 29.489 29.826 29.525 ;
     RECT  21.315 29.525 29.697 29.669 ;
     RECT  30.744 29.219 31.338 29.759 ;
     RECT  22.392 29.669 29.697 29.795 ;
     RECT  22.392 29.795 23.202 29.867 ;
     RECT  22.824 29.867 23.202 29.939 ;
     RECT  24.015 29.795 29.697 29.939 ;
     RECT  2.415 22.157 2.697 29.987 ;
     RECT  5.115 21.965 5.397 29.987 ;
     RECT  7.815 22.235 8.097 29.987 ;
     RECT  10.515 21.839 10.797 29.987 ;
     RECT  13.215 21.569 13.497 29.987 ;
     RECT  15.915 27.743 16.197 29.987 ;
     RECT  18.615 29.255 18.897 29.987 ;
     RECT  21.315 29.669 21.597 29.987 ;
     RECT  24.015 29.939 26.997 29.987 ;
     RECT  27.756 29.939 29.697 29.987 ;
     RECT  31.284 29.759 31.338 30.029 ;
     RECT  24.015 29.987 26.874 30.065 ;
     RECT  24.015 30.065 25.434 30.101 ;
     RECT  27.756 29.987 29.505 30.101 ;
     RECT  31.32 30.029 31.338 30.101 ;
     RECT  27.756 30.101 27.81 30.137 ;
     RECT  28.872 30.101 29.505 30.137 ;
     RECT  32.292 29.021 32.31 30.137 ;
     RECT  24.015 30.101 24.606 30.173 ;
     RECT  25.416 30.101 25.434 30.173 ;
     RECT  26.568 30.065 26.874 30.173 ;
     RECT  22.824 29.939 22.842 30.209 ;
     RECT  26.568 30.173 26.805 30.209 ;
     RECT  27.792 30.137 27.81 30.209 ;
     RECT  2.415 29.987 2.505 30.257 ;
     RECT  5.115 29.987 5.205 30.257 ;
     RECT  7.815 29.987 7.905 30.257 ;
     RECT  10.515 29.987 10.605 30.257 ;
     RECT  13.215 29.987 13.305 30.257 ;
     RECT  15.915 29.987 16.005 30.257 ;
     RECT  18.615 29.987 18.705 30.257 ;
     RECT  21.315 29.987 21.405 30.257 ;
     RECT  24.015 30.173 24.105 30.257 ;
     RECT  26.715 30.209 26.805 30.257 ;
     RECT  29.415 30.137 29.505 30.257 ;
    LAYER M4 ;
     RECT  0.06 15.984 0.137 22.44 ;
     RECT  0.06 6.384 0.209 12.456 ;
     RECT  0.209 6.384 0.533 12.36 ;
     RECT  0.137 15.984 0.533 22.344 ;
     RECT  0.533 6.768 0.569 12.36 ;
     RECT  0.533 15.984 0.569 22.248 ;
     RECT  0.569 6.864 2.408 12.36 ;
     RECT  0.569 15.984 2.408 22.152 ;
     RECT  2.408 2.148 2.512 30.252 ;
     RECT  2.512 2.418 2.704 29.982 ;
     RECT  2.704 16.368 2.873 22.104 ;
     RECT  2.704 6.864 4.025 12.36 ;
     RECT  2.873 16.368 4.025 22.056 ;
     RECT  4.025 16.512 4.061 22.056 ;
     RECT  4.025 6.96 5.108 12.36 ;
     RECT  4.061 16.56 5.108 22.056 ;
     RECT  5.108 2.148 5.212 30.252 ;
     RECT  5.212 2.418 5.404 29.982 ;
     RECT  5.404 16.56 6.757 22.056 ;
     RECT  5.404 6.96 7.808 12.36 ;
     RECT  6.757 16.512 7.808 22.056 ;
     RECT  7.808 2.148 7.912 30.252 ;
     RECT  7.912 2.418 8.104 29.982 ;
     RECT  8.104 16.656 9.065 16.68 ;
     RECT  8.104 7.104 9.389 12.36 ;
     RECT  9.389 7.632 9.497 12.36 ;
     RECT  9.497 7.632 10.508 11.208 ;
     RECT  9.497 12.288 10.508 12.36 ;
     RECT  8.104 18 10.508 21.528 ;
     RECT  10.508 2.148 10.612 30.252 ;
     RECT  10.612 2.418 10.804 29.982 ;
     RECT  10.804 8.208 10.901 11.304 ;
     RECT  10.901 8.208 11.117 11.208 ;
     RECT  10.804 18 11.117 21.528 ;
     RECT  11.117 18 11.657 18.024 ;
     RECT  11.117 8.448 11.765 11.208 ;
     RECT  11.765 8.496 11.873 11.208 ;
     RECT  11.941 7.44 12.025 7.464 ;
     RECT  11.873 10.944 12.589 11.208 ;
     RECT  10.804 12.288 12.589 12.36 ;
     RECT  11.845 16.32 13.093 16.344 ;
     RECT  11.873 8.496 13.208 9.672 ;
     RECT  12.589 10.944 13.208 12.36 ;
     RECT  13.093 15.84 13.208 16.344 ;
     RECT  13.021 17.472 13.208 17.496 ;
     RECT  11.117 19.488 13.208 21.528 ;
     RECT  13.208 2.148 13.312 30.252 ;
     RECT  13.312 2.418 13.504 29.982 ;
     RECT  13.504 13.68 14.429 14.232 ;
     RECT  13.504 8.496 14.821 9 ;
     RECT  13.504 15.84 14.821 16.344 ;
     RECT  13.504 10.848 14.965 12.312 ;
     RECT  14.821 8.256 14.972 9 ;
     RECT  14.965 10.704 14.972 12.312 ;
     RECT  14.972 8.256 15.013 12.312 ;
     RECT  15.013 7.968 15.181 12.312 ;
     RECT  15.181 7.968 15.289 12.504 ;
     RECT  15.289 7.344 15.397 12.504 ;
     RECT  14.429 14.208 15.469 14.232 ;
     RECT  15.253 6.288 15.908 6.312 ;
     RECT  15.397 7.344 15.908 13.128 ;
     RECT  15.469 14.208 15.908 14.76 ;
     RECT  14.821 15.744 15.908 16.344 ;
     RECT  13.504 17.472 15.908 18.264 ;
     RECT  13.504 19.584 15.908 21.528 ;
     RECT  15.908 2.148 16.012 30.252 ;
     RECT  16.012 2.418 16.204 29.982 ;
     RECT  16.204 15.744 16.373 22.2 ;
     RECT  16.373 15.744 16.409 16.344 ;
     RECT  16.204 14.736 16.517 14.76 ;
     RECT  16.204 6.816 17.269 12.504 ;
     RECT  17.233 13.584 17.269 13.608 ;
     RECT  16.409 16.08 17.42 16.344 ;
     RECT  16.373 17.328 17.42 22.2 ;
     RECT  17.305 14.784 17.485 14.808 ;
     RECT  17.42 16.08 17.525 22.2 ;
     RECT  17.485 14.784 17.845 15 ;
     RECT  16.204 23.328 18.025 23.544 ;
     RECT  16.204 24.528 18.025 24.552 ;
     RECT  17.996 27.84 18.037 27.864 ;
     RECT  18.025 23.328 18.169 24.552 ;
     RECT  17.269 6.816 18.373 13.608 ;
     RECT  17.845 14.688 18.373 15 ;
     RECT  18.373 6.816 18.608 15 ;
     RECT  17.525 16.08 18.608 18.168 ;
     RECT  17.525 19.392 18.608 22.2 ;
     RECT  18.169 23.328 18.608 25.272 ;
     RECT  17.845 26.256 18.608 26.76 ;
     RECT  18.037 27.84 18.608 28.296 ;
     RECT  18.608 2.148 18.712 30.252 ;
     RECT  18.712 2.418 18.904 29.982 ;
     RECT  18.904 28.272 18.965 28.296 ;
     RECT  18.904 8.256 19.109 23.64 ;
     RECT  19.109 8.256 19.217 23.352 ;
     RECT  18.904 26.256 19.469 26.28 ;
     RECT  19.217 8.4 19.475 23.352 ;
     RECT  19.475 22.704 19.721 23.352 ;
     RECT  18.904 25.248 20.077 25.272 ;
     RECT  19.475 8.4 20.153 21.672 ;
     RECT  20.153 8.4 20.185 13.608 ;
     RECT  18.904 6.816 20.257 6.84 ;
     RECT  20.185 8.304 20.329 13.608 ;
     RECT  20.257 6.816 20.365 6.888 ;
     RECT  20.365 6.768 20.401 6.888 ;
     RECT  20.221 5.184 20.492 5.208 ;
     RECT  20.401 6.672 20.492 6.888 ;
     RECT  20.492 5.184 20.533 6.888 ;
     RECT  20.153 14.976 20.869 21.672 ;
     RECT  19.721 22.992 20.869 23.352 ;
     RECT  20.293 29.376 21.085 29.4 ;
     RECT  20.533 5.04 21.157 6.888 ;
     RECT  20.329 7.968 21.157 13.608 ;
     RECT  21.157 5.04 21.308 13.608 ;
     RECT  20.869 14.976 21.308 23.352 ;
     RECT  20.077 25.248 21.308 26.232 ;
     RECT  20.725 27.888 21.308 27.912 ;
     RECT  21.085 29.232 21.308 29.4 ;
     RECT  21.308 2.148 21.412 30.252 ;
     RECT  21.412 2.418 21.604 29.982 ;
     RECT  21.604 24.672 21.629 25.32 ;
     RECT  21.629 24.672 21.665 25.272 ;
     RECT  21.604 10.848 21.809 23.304 ;
     RECT  21.809 10.848 22.097 22.008 ;
     RECT  21.604 29.232 22.205 29.256 ;
     RECT  21.604 3.936 22.669 3.96 ;
     RECT  21.604 5.04 22.669 5.064 ;
     RECT  22.097 13.584 22.781 22.008 ;
     RECT  22.669 3.936 22.853 5.064 ;
     RECT  21.604 6.096 22.921 9 ;
     RECT  22.097 10.848 22.993 12.6 ;
     RECT  21.604 27.36 22.997 27.912 ;
     RECT  22.997 27.408 23.065 27.912 ;
     RECT  22.781 14.688 23.077 22.008 ;
     RECT  22.921 6.096 23.101 9.144 ;
     RECT  23.101 5.28 23.569 9.144 ;
     RECT  22.993 10.176 23.569 12.6 ;
     RECT  22.781 13.584 23.569 13.608 ;
     RECT  21.809 23.04 23.749 23.304 ;
     RECT  23.077 14.688 23.821 22.056 ;
     RECT  23.749 23.04 23.821 23.4 ;
     RECT  23.065 27.408 23.821 27.96 ;
     RECT  23.821 14.688 23.893 23.4 ;
     RECT  23.821 27.408 23.893 28.2 ;
     RECT  23.893 27.408 23.965 28.248 ;
     RECT  22.777 29.472 23.965 29.496 ;
     RECT  23.569 2.496 24.008 2.52 ;
     RECT  22.853 3.936 24.008 3.96 ;
     RECT  23.569 5.28 24.008 13.608 ;
     RECT  23.893 14.688 24.008 23.592 ;
     RECT  21.665 24.72 24.008 25.272 ;
     RECT  23.965 27.408 24.008 29.496 ;
     RECT  24.008 2.148 24.112 30.252 ;
     RECT  24.112 2.256 24.304 29.982 ;
     RECT  24.304 2.256 25.091 29.064 ;
     RECT  25.091 2.352 25.331 29.064 ;
     RECT  25.331 25.44 25.373 29.064 ;
     RECT  25.331 2.352 25.589 24.312 ;
     RECT  25.589 14.928 26.485 24.312 ;
     RECT  25.373 25.44 26.485 29.016 ;
     RECT  25.589 2.352 26.708 13.848 ;
     RECT  26.485 14.928 26.708 29.016 ;
     RECT  26.708 2.148 26.812 30.252 ;
     RECT  26.812 2.418 27.004 29.982 ;
     RECT  27.004 2.736 27.173 2.856 ;
     RECT  27.173 2.832 27.209 2.856 ;
     RECT  27.004 5.28 27.461 12.504 ;
     RECT  27.004 13.728 27.677 29.16 ;
     RECT  27.677 13.728 27.785 29.064 ;
     RECT  27.785 13.728 28.073 18.984 ;
     RECT  27.785 20.16 28.073 29.064 ;
     RECT  28.073 13.728 28.249 18.6 ;
     RECT  27.461 5.472 28.285 12.504 ;
     RECT  28.249 13.632 28.285 18.6 ;
     RECT  27.004 3.84 28.393 4.152 ;
     RECT  28.393 3.84 28.429 4.248 ;
     RECT  28.285 5.472 28.429 18.6 ;
     RECT  28.073 20.16 28.933 20.232 ;
     RECT  28.429 3.84 29.041 18.6 ;
     RECT  29.041 3.84 29.149 18.84 ;
     RECT  28.933 20.064 29.149 20.232 ;
     RECT  29.149 3.84 29.408 20.232 ;
     RECT  28.073 21.504 29.408 29.064 ;
     RECT  29.408 2.148 29.512 30.252 ;
     RECT  29.512 2.418 29.704 29.982 ;
     RECT  29.704 20.064 30.733 29.016 ;
     RECT  29.704 3.792 30.769 18.408 ;
     RECT  30.769 3.792 30.805 18.696 ;
     RECT  30.805 3.792 31.273 18.792 ;
     RECT  30.733 19.92 31.273 29.064 ;
     RECT  31.273 3.792 32.364 29.064 ;
    LAYER M5 ;
     RECT  2.4 2.137 2.52 2.151 ;
     RECT  5.1 2.137 5.22 2.151 ;
     RECT  7.8 2.137 7.92 2.151 ;
     RECT  10.5 2.137 10.62 2.151 ;
     RECT  13.2 2.137 13.32 2.151 ;
     RECT  15.9 2.137 16.02 2.151 ;
     RECT  18.6 2.137 18.72 2.151 ;
     RECT  21.3 2.137 21.42 2.151 ;
     RECT  24 2.137 24.12 2.151 ;
     RECT  26.7 2.137 26.82 2.151 ;
     RECT  29.4 2.137 29.52 2.151 ;
     RECT  24 2.151 24.312 2.245 ;
     RECT  24 2.245 25.08 4.403 ;
     RECT  21.3 2.151 21.612 5.029 ;
     RECT  26.7 2.151 27.012 5.461 ;
     RECT  20.544 5.029 21.612 5.747 ;
     RECT  29.4 2.151 29.712 6.613 ;
     RECT  26.7 5.461 27.24 6.709 ;
     RECT  26.7 6.709 27.288 6.851 ;
     RECT  29.28 6.613 29.712 6.851 ;
     RECT  21.3 5.747 21.612 7.381 ;
     RECT  11.856 0.016 11.976 7.475 ;
     RECT  24 4.403 24.312 7.621 ;
     RECT  15.9 2.151 16.212 7.957 ;
     RECT  9.456 8.245 9.48 8.483 ;
     RECT  17.424 6.805 17.448 8.531 ;
     RECT  29.4 6.851 29.712 8.533 ;
     RECT  29.184 8.533 29.712 8.675 ;
     RECT  21.168 7.381 21.612 9.493 ;
     RECT  15.024 7.957 16.212 9.779 ;
     RECT  18.6 2.151 18.912 10.069 ;
     RECT  20.496 9.493 21.612 10.883 ;
     RECT  24 7.621 24.456 11.173 ;
     RECT  15.36 9.779 16.212 11.459 ;
     RECT  24 11.173 25.032 11.507 ;
     RECT  18.6 10.069 19.032 12.179 ;
     RECT  15.408 11.459 16.212 13.139 ;
     RECT  24 11.507 24.312 13.141 ;
     RECT  17.52 10.789 17.544 13.427 ;
     RECT  18.6 12.179 18.912 13.621 ;
     RECT  20.592 10.883 21.612 13.621 ;
     RECT  24 13.141 24.408 13.667 ;
     RECT  18.6 13.621 21.612 14.197 ;
     RECT  18.384 14.197 21.612 14.291 ;
     RECT  18.384 14.291 18.912 14.723 ;
     RECT  29.4 8.675 29.712 15.541 ;
     RECT  14.832 14.197 14.856 15.779 ;
     RECT  29.4 15.541 30.36 15.827 ;
     RECT  11.856 7.475 11.88 16.355 ;
     RECT  18.6 14.723 18.912 16.981 ;
     RECT  20.592 14.291 21.612 16.981 ;
     RECT  24 13.667 24.312 17.461 ;
     RECT  15.9 13.139 16.212 17.653 ;
     RECT  17.472 16.501 17.496 17.653 ;
     RECT  15.9 17.653 17.496 17.699 ;
     RECT  22.608 16.357 22.632 17.699 ;
     RECT  2.4 2.151 2.712 17.845 ;
     RECT  2.4 17.845 2.904 18.035 ;
     RECT  18.6 16.981 21.612 18.419 ;
     RECT  24 17.461 24.792 18.757 ;
     RECT  15.9 17.699 17.16 18.851 ;
     RECT  0.144 19.045 0.168 20.099 ;
     RECT  22.656 18.037 22.68 20.293 ;
     RECT  18.6 18.419 18.912 20.389 ;
     RECT  15.9 18.851 16.212 20.485 ;
     RECT  24 18.757 25.128 20.579 ;
     RECT  20.592 18.419 21.612 21.155 ;
     RECT  24 20.579 25.08 21.251 ;
     RECT  20.688 21.155 21.612 21.395 ;
     RECT  24 21.251 24.792 21.395 ;
     RECT  0.144 21.445 0.168 21.589 ;
     RECT  0.144 21.589 0.264 21.635 ;
     RECT  24 21.395 24.6 21.635 ;
     RECT  22.656 20.293 22.872 21.637 ;
     RECT  24 21.635 24.504 21.637 ;
     RECT  22.656 21.637 24.504 21.683 ;
     RECT  0.24 21.635 0.264 21.731 ;
     RECT  22.848 21.683 24.504 21.923 ;
     RECT  15.9 20.485 16.344 22.165 ;
     RECT  18.6 20.389 19.464 22.739 ;
     RECT  15.9 22.165 17.16 23.555 ;
     RECT  23.088 21.923 24.504 25.189 ;
     RECT  21.3 21.395 21.612 25.285 ;
     RECT  20.496 25.285 21.612 26.243 ;
     RECT  18.6 22.739 18.912 26.725 ;
     RECT  23.088 25.189 25.32 26.819 ;
     RECT  23.088 26.819 24.408 27.971 ;
     RECT  18.048 26.725 18.912 28.307 ;
     RECT  32.208 28.213 32.232 28.499 ;
     RECT  24 27.971 24.408 28.979 ;
     RECT  2.4 18.035 2.712 30.249 ;
     RECT  5.1 2.151 5.412 30.249 ;
     RECT  7.8 2.151 8.112 30.249 ;
     RECT  10.5 2.151 10.812 30.249 ;
     RECT  13.2 2.151 13.512 30.249 ;
     RECT  15.9 23.555 16.212 30.249 ;
     RECT  18.6 28.307 18.912 30.249 ;
     RECT  21.3 26.243 21.612 30.249 ;
     RECT  24 28.979 24.312 30.249 ;
     RECT  26.7 6.851 27.012 30.249 ;
     RECT  29.4 15.827 29.712 30.249 ;
     RECT  2.4 30.249 2.52 30.263 ;
     RECT  5.1 30.249 5.22 30.263 ;
     RECT  7.8 30.249 7.92 30.263 ;
     RECT  10.5 30.249 10.62 30.263 ;
     RECT  13.2 30.249 13.32 30.263 ;
     RECT  15.9 30.249 16.02 30.263 ;
     RECT  18.6 30.249 18.72 30.263 ;
     RECT  21.3 30.249 21.42 30.263 ;
     RECT  24 30.249 24.12 30.263 ;
     RECT  26.7 30.249 26.82 30.263 ;
     RECT  29.4 30.249 29.52 30.263 ;
     RECT  10.62 2.137 11.856 2.151 ;
     RECT  11.976 2.137 13.2 7.475 ;
     RECT  10.812 2.151 11.856 16.355 ;
     RECT  16.212 6.805 17.424 8.531 ;
     RECT  17.448 6.805 18.6 8.531 ;
     RECT  11.88 7.475 13.2 16.355 ;
     RECT  13.512 7.957 15.024 9.779 ;
     RECT  8.112 8.245 9.456 8.483 ;
     RECT  9.48 8.245 10.5 8.483 ;
     RECT  19.032 10.069 20.496 10.883 ;
     RECT  16.212 10.789 17.52 13.427 ;
     RECT  17.544 10.789 18.6 13.427 ;
     RECT  18.912 12.179 19.032 13.621 ;
     RECT  15.408 13.139 15.9 14.197 ;
     RECT  18.384 13.427 18.6 14.197 ;
     RECT  13.512 14.197 14.832 15.779 ;
     RECT  14.856 14.197 15.9 15.779 ;
     RECT  21.612 16.357 22.608 17.699 ;
     RECT  22.632 16.357 24 17.699 ;
     RECT  16.212 16.501 17.472 17.653 ;
     RECT  17.496 16.501 18.6 17.699 ;
     RECT  17.16 17.699 18.6 18.851 ;
     RECT  21.612 17.699 24 18.037 ;
     RECT  21.612 18.037 22.656 21.683 ;
     RECT  22.68 18.037 24 20.293 ;
     RECT  0.144 20.099 0.168 21.445 ;
     RECT  22.872 20.293 24 21.637 ;
     RECT  19.464 20.389 20.592 21.155 ;
     RECT  19.464 21.155 20.688 21.395 ;
     RECT  21.612 21.683 22.848 21.923 ;
     RECT  21.612 21.923 23.088 27.971 ;
     RECT  17.16 22.165 18.6 23.555 ;
     RECT  25.32 25.189 26.7 26.819 ;
  END
END ot_hbm_native_fence_bank128
END LIBRARY
